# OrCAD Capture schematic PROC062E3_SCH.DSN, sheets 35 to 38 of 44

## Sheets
35 34.SERDES & DISPLAY INTERFACE: size C; title: SERDES & DISPLAY INTERFACE
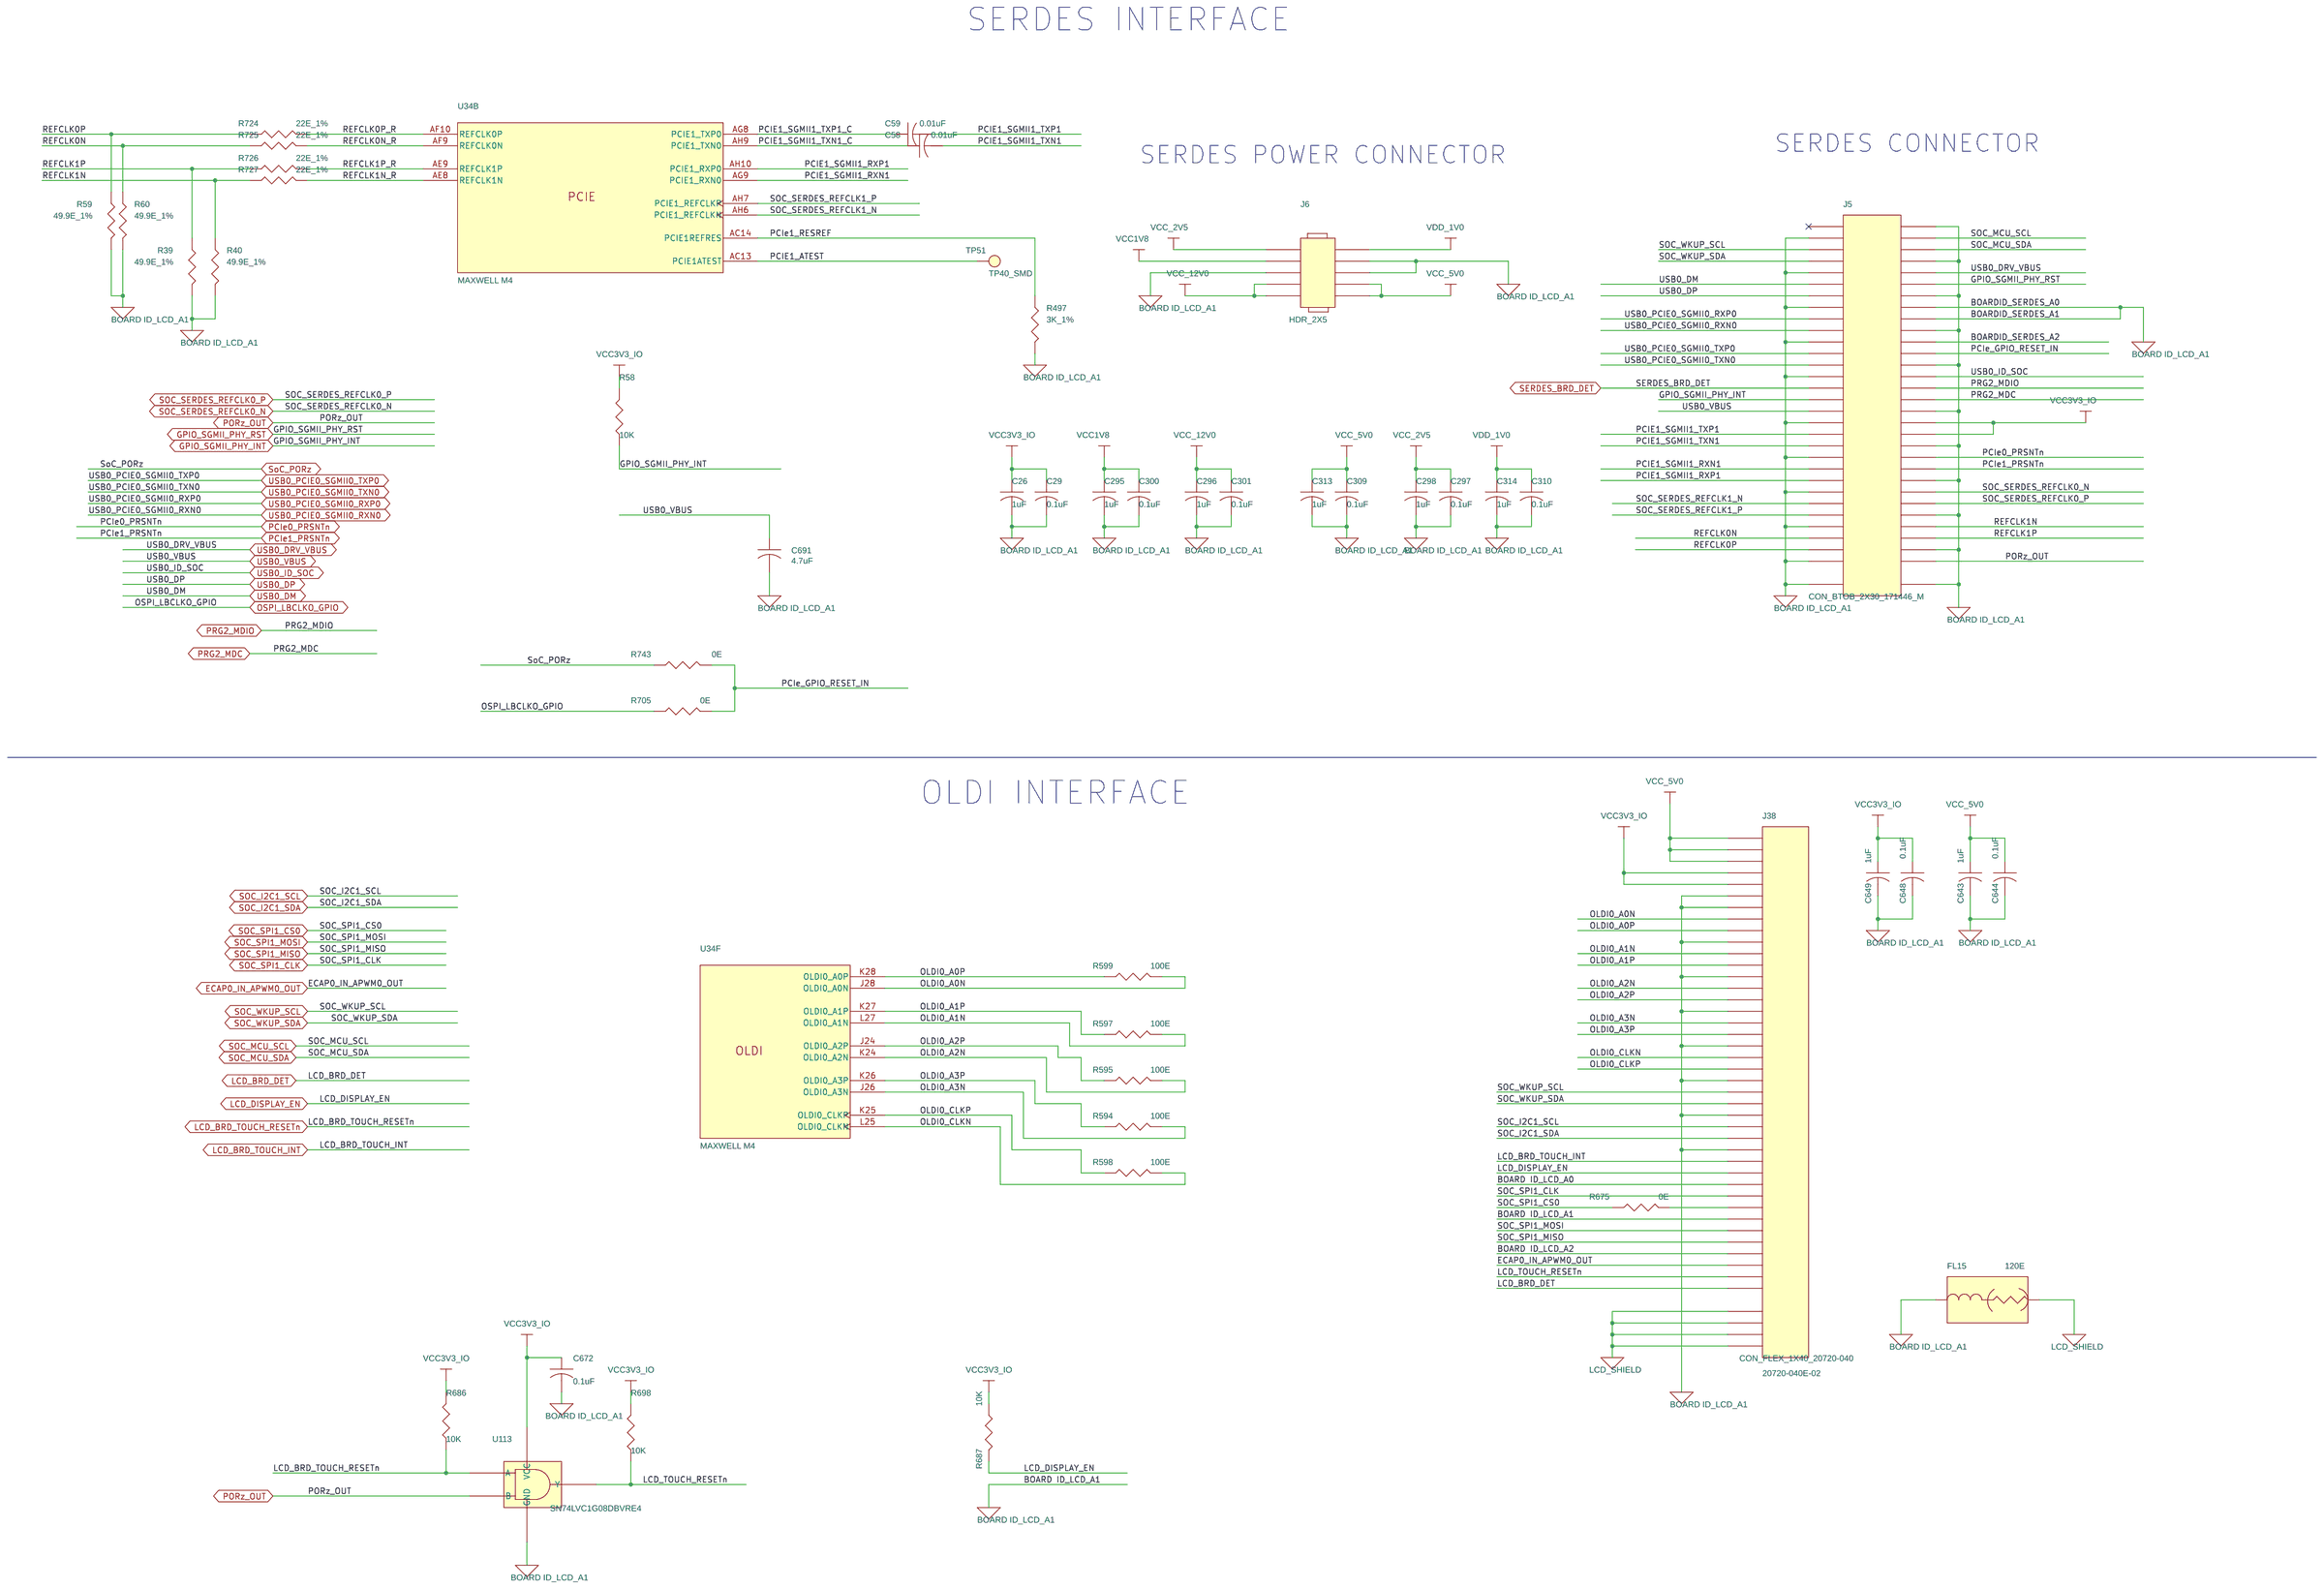
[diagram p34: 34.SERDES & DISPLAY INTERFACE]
36 36.ETHERNET PHY CLOCK BUFFER: size C; title: ETHERNET PHY CLOCK GENERATOR
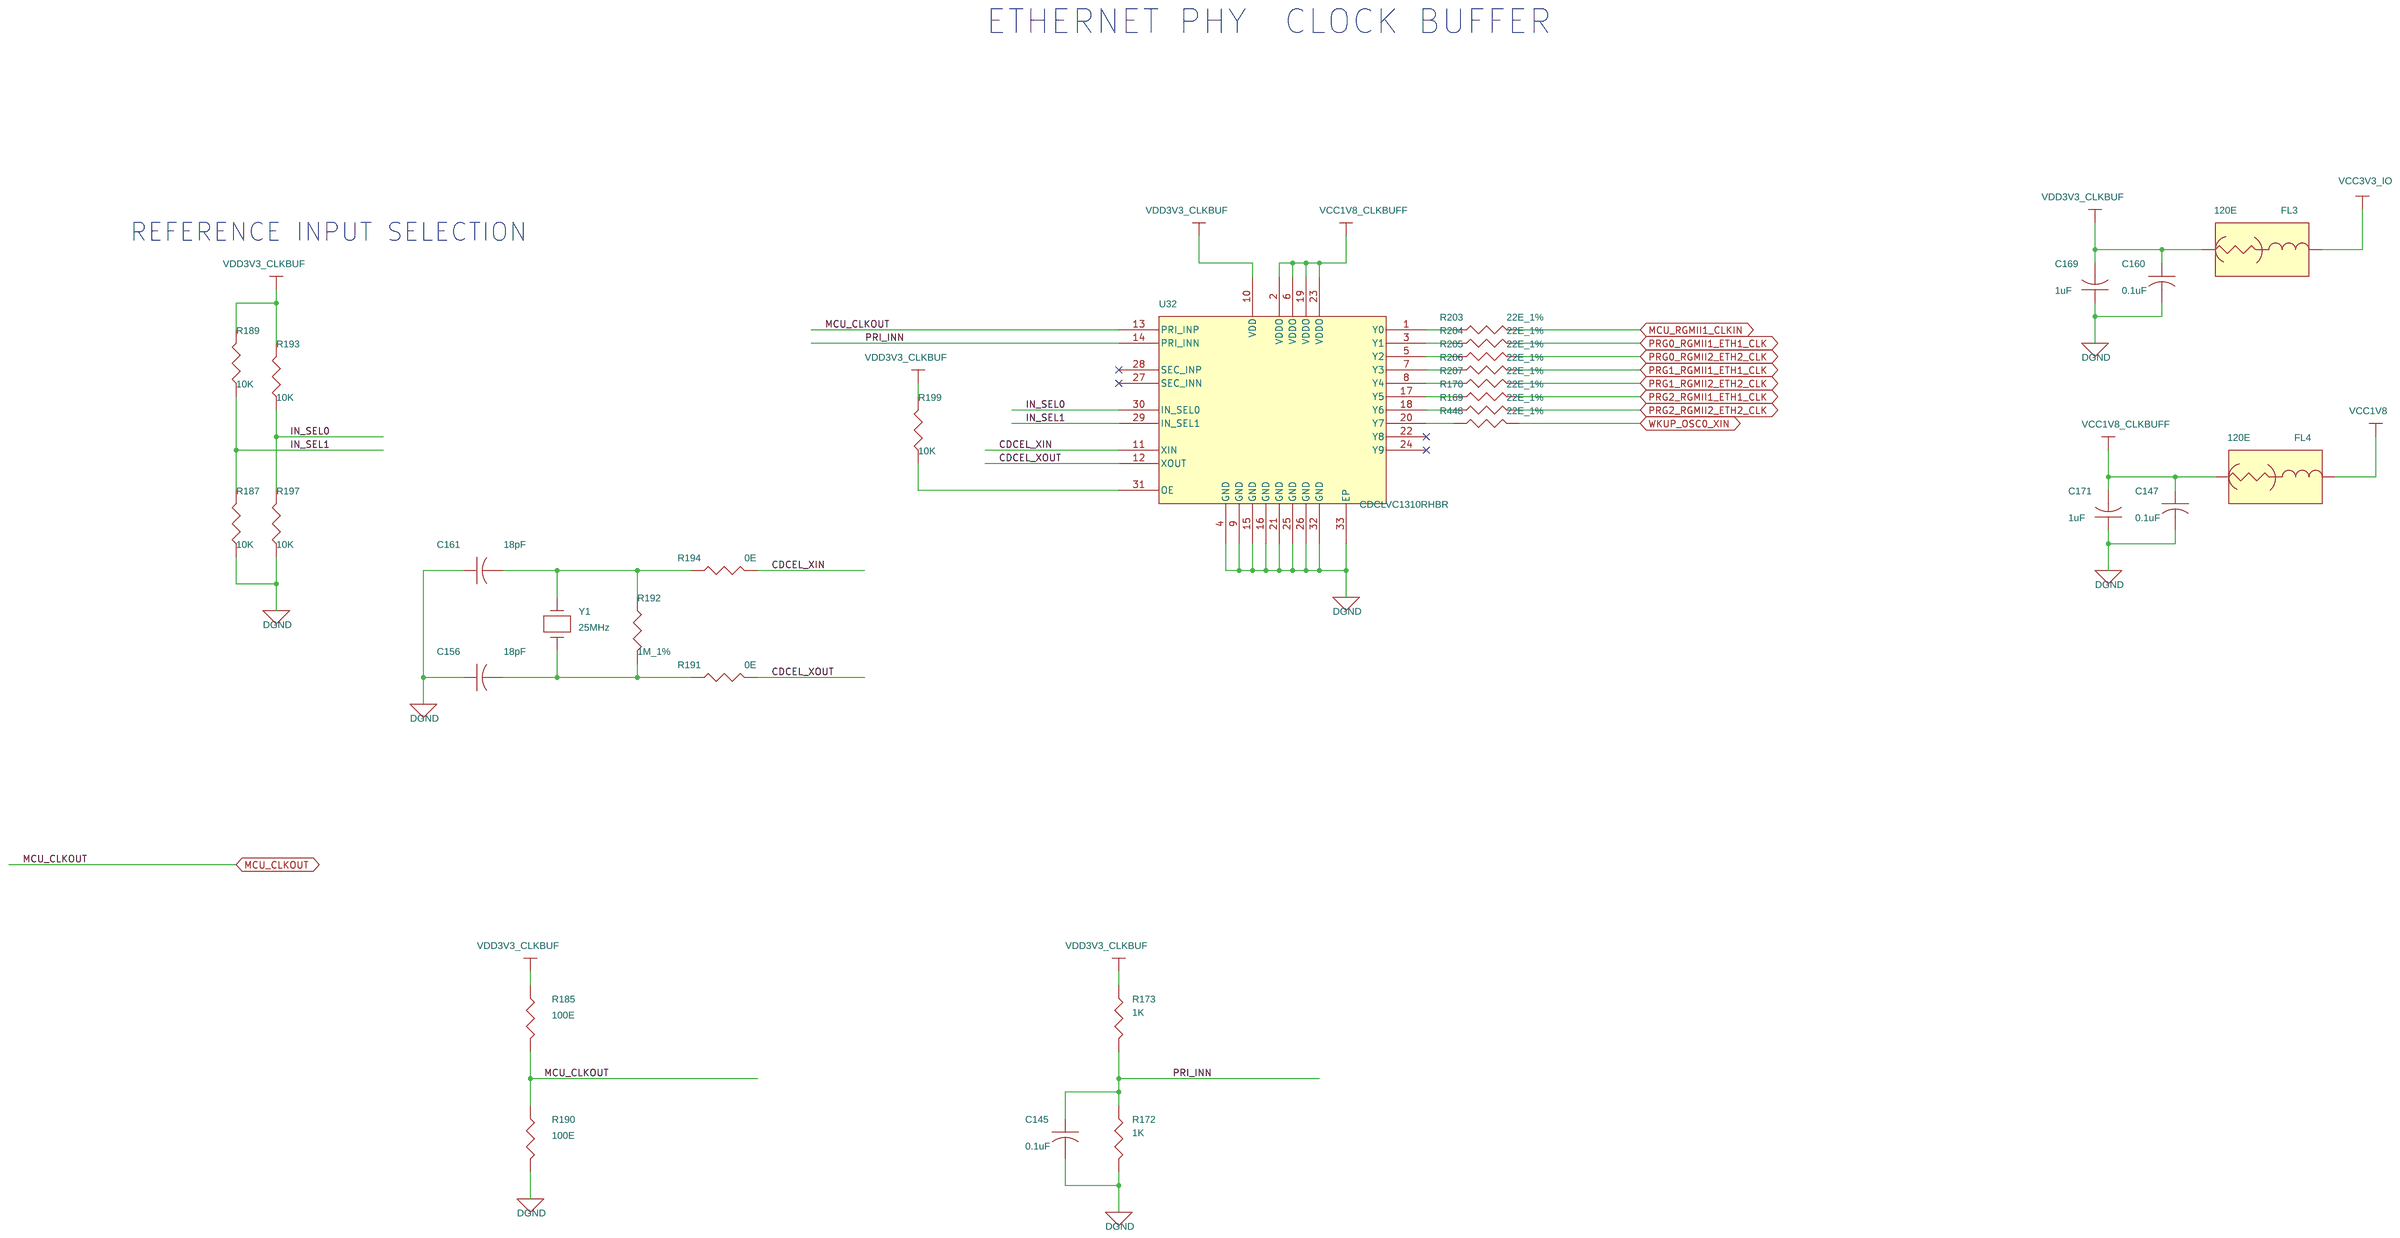
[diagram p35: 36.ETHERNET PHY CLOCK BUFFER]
37 37. ETHERNET LED's: size C; title: ETHERNET LEDs
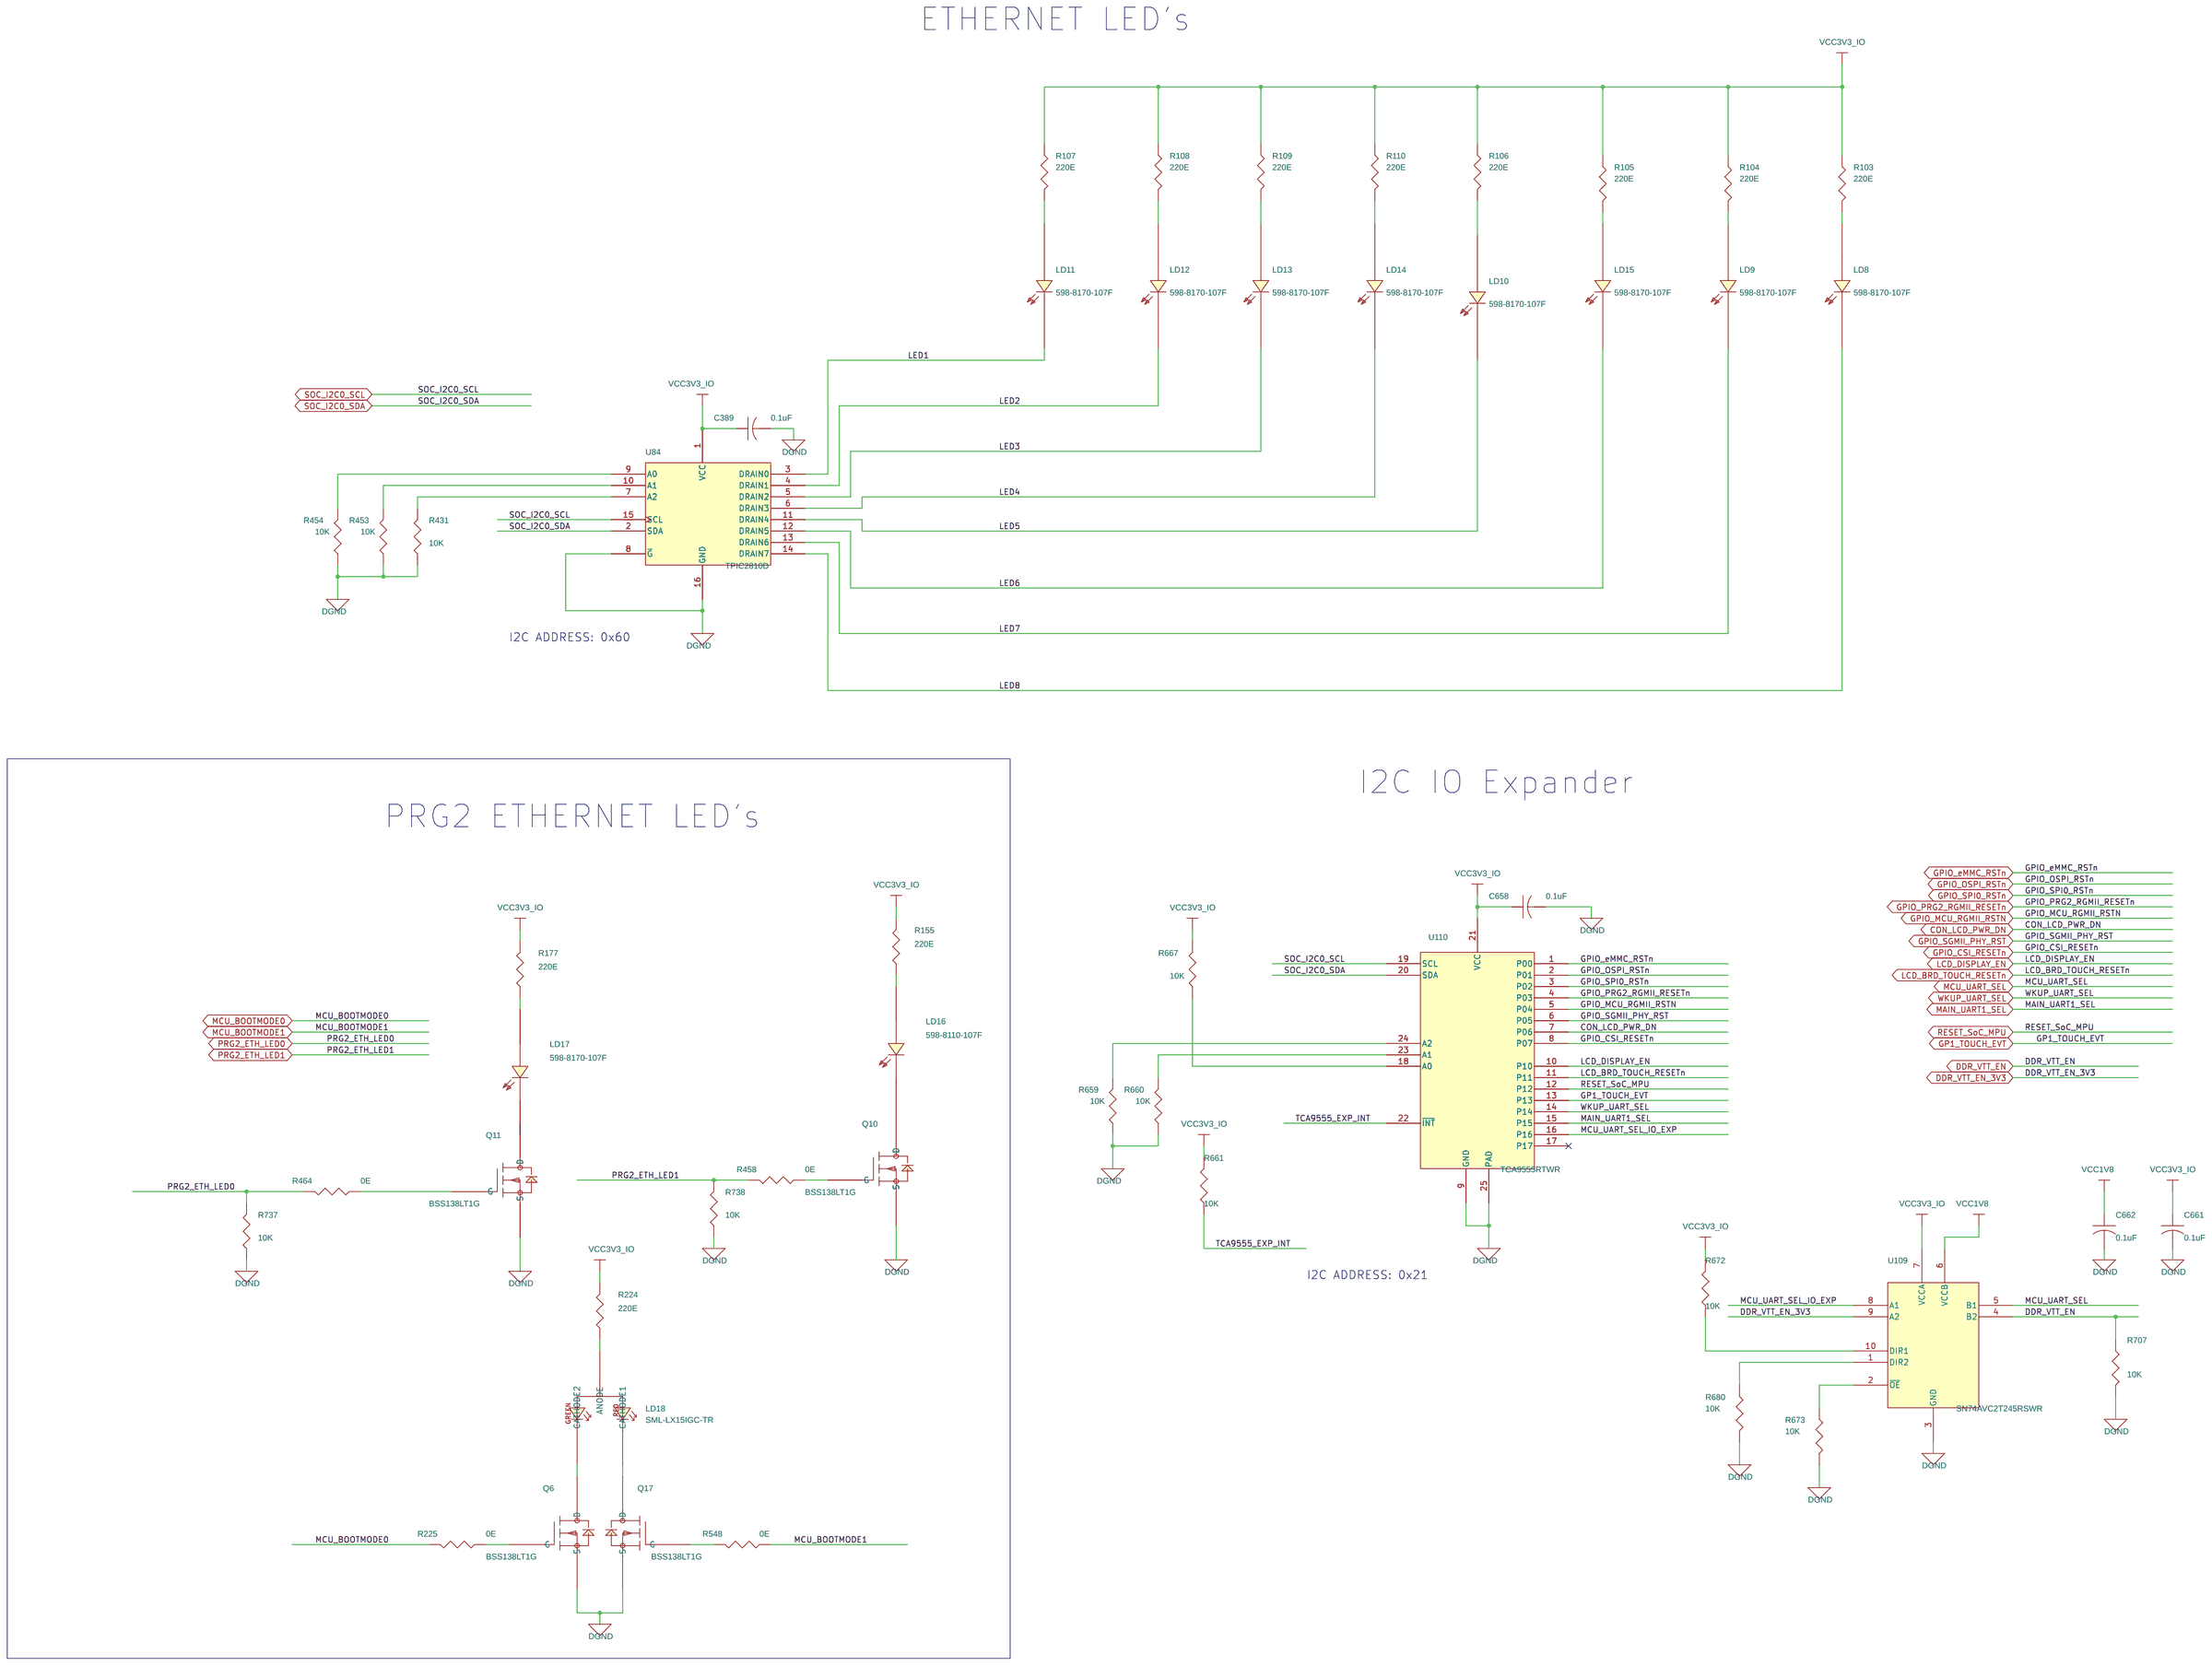
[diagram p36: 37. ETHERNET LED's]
38 38. TEST  HEADER: size C; title: TEST HEADER

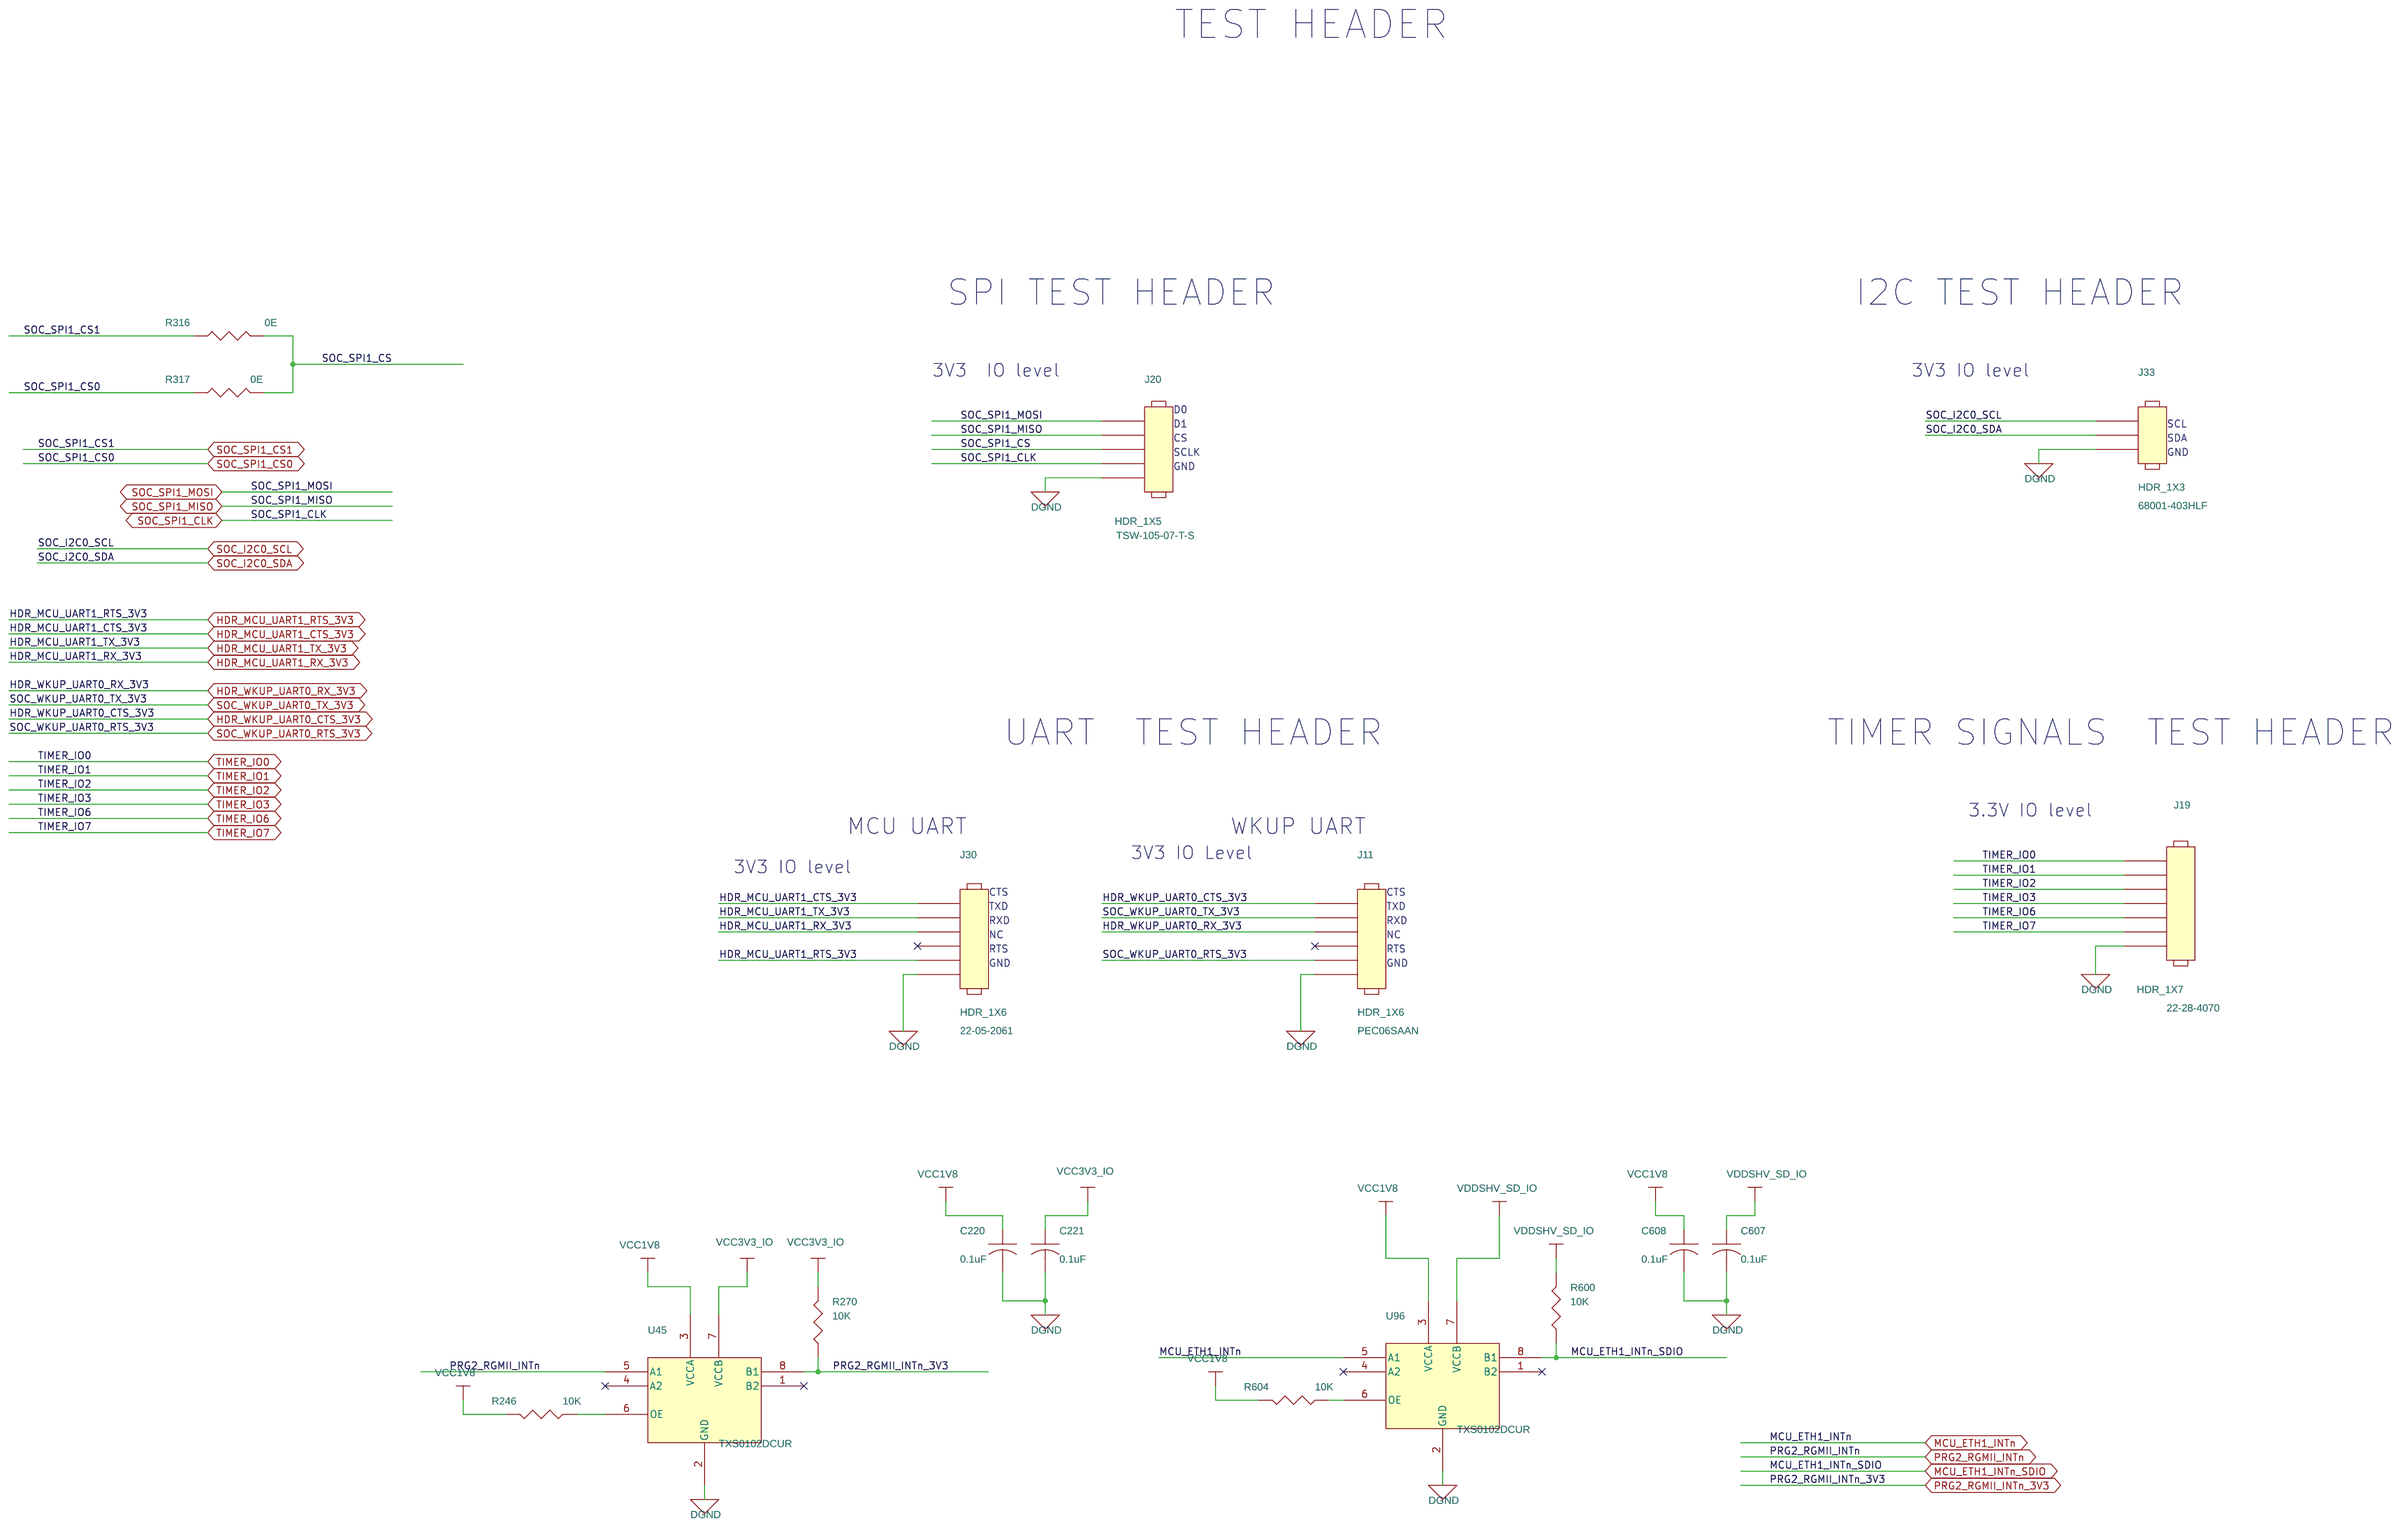
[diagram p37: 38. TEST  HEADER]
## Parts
sheet 34.SERDES & DISPLAY INTERFACE
C26  1uF  [CAP0402_0-75]
C29  0.1uF  [CAP0201_0-5]
C58  0.01uF  [CAP0402_0-75]
C59  0.01uF  [CAP0402_0-75]
C295  1uF  [CAP0402_0-75]
C296  1uF  [CAP0402_0-75]
C297  0.1uF  [CAP0201_0-5]
C298  1uF  [CAP0402_0-75]
C300  0.1uF  [CAP0201_0-5]
C301  0.1uF  [CAP0201_0-5]
C309  0.1uF  [CAP0201_0-5]
C310  0.1uF  [CAP0201_0-5]
C313  1uF  [CAP0402_0-75]
C314  1uF  [CAP0402_0-75]
C643  1uF  [CAP0402_0-75]
C644  0.1uF  [CAP0201_0-5]
C648  0.1uF  [CAP0201_0-5]
C649  1uF  [CAP0402_0-75]
C672  0.1uF  [CAP0201_0-5]
C691  4.7uF  [CAP0402_0-75]
FL15  120E  [EMIFIL_BLM15A_0402_0-6]
J5  CON_BTOB_2X30_171446_M  [CON_BTOB2X30_171446_P_S_S_5-5]
J6  HDR_2X5  [HDR_2X5_TFC-105-01-D-A_S_T_5-6]
J38  CON_FLEX_1X40_20720-040  [CON_FLEX1X40_20720-040_S_R_S_2]
R39  49.9E_1%  [RES0201]
R40  49.9E_1%  [RES0201]
R58  10K  [RES0402_0-5]
R59  49.9E_1%  [RES0201]
R60  49.9E_1%  [RES0201]
R497  3K_1%  [RES0402_0-5]
R594  100E  [RES0201]
R595  100E  [RES0201]
R597  100E  [RES0201]
R598  100E  [RES0201]
R599  100E  [RES0201]
R675  0E  [RES0402_0-5]
R686  10K  [RES0402_0-5]
R687  10K  [RES0402_0-5]
R698  10K  [RES0402_0-5]
R705  0E  [RES0402_0-5]
R724  22E_1%  [RES0402]
R725  22E_1%  [RES0402]
R726  22E_1%  [RES0402]
R727  22E_1%  [RES0402]
R743  0E  [RES0402_0-5]
TP51  TP40_SMD  [TP40_SMD]
U113  SN74LVC1G08DBVRE4  [SOT23-5]
sheet 35. CSI,GPMC/DSS INTERFACE
U34  MAXWELL M4  [BGA784_31-49_910X910_1-7]  (sections A,B,C,D,E,F,G,H,I,J,K,L,M,N,O,P,Q,R,S)
sheet 36.ETHERNET PHY CLOCK BUFFER
C145  0.1uF  [CAP0201_0-5]
C147  0.1uF  [CAP0201_0-5]
C156  18pF  [CAP0402_0-75]
C160  0.1uF  [CAP0201_0-5]
C161  18pF  [CAP0402_0-75]
C169  1uF  [CAP0402_0-75]
C171  1uF  [CAP0402_0-75]
FL3  120E  [EMIFIL_BLM15A_0402_0-6]
FL4  120E  [EMIFIL_BLM15A_0402_0-6]
R169  22E_1%  [RES0402]
R170  22E_1%  [RES0402]
R172  1K  [RES0201]
R173  1K  [RES0201]
R185  100E  [RES0402_0-5]
R187  10K  [RES0402_0-5]
R189  10K  [RES0402_0-5]
R190  100E  [RES0402_0-5]
R191  0E  [RES0402_0-5]
R192  1M_1%  [RES0402]
R193  10K  [RES0402_0-5]
R194  0E  [RES0402_0-5]
R197  10K  [RES0402_0-5]
R199  10K  [RES0402_0-5]
R203  22E_1%  [RES0402]
R204  22E_1%  [RES0402]
R205  22E_1%  [RES0402]
R206  22E_1%  [RES0402]
R207  22E_1%  [RES0402]
R448  22E_1%  [RES0402]
U32  CDCLVC1310RHBR  [QFN32_19-68_200X200_1]
Y1  25MHz  [XTAL_ABM3_210X130_SMD]
sheet 37. ETHERNET LED's
C389  0.1uF  [CAP0201_0-5]
C658  0.1uF  [CAP0201_0-5]
C661  0.1uF  [CAP0201_0-5]
C662  0.1uF  [CAP0201_0-5]
LD8  598-8170-107F  [LED_0805_0-7]
LD9  598-8170-107F  [LED_0805_0-7]
LD10  598-8170-107F  [LED_0805_0-7]
LD11  598-8170-107F  [LED_0805_0-7]
LD12  598-8170-107F  [LED_0805_0-7]
LD13  598-8170-107F  [LED_0805_0-7]
LD14  598-8170-107F  [LED_0805_0-7]
LD15  598-8170-107F  [LED_0805_0-7]
LD16  598-8110-107F  [LED_0805]
LD17  598-8170-107F  [LED_0805_0-7]
LD18  SML-LX15IGC-TR  [LED3_SML-LX15IGC_120X120_SMD_1]
Q6  BSS138LT1G  [SOT23-123]
Q10  BSS138LT1G  [SOT23-123]
Q11  BSS138LT1G  [SOT23-123]
Q17  BSS138LT1G  [SOT23-123]
R103  220E  [RES0402_0-5]
R104  220E  [RES0402_0-5]
R105  220E  [RES0402_0-5]
R106  220E  [RES0402_0-5]
R107  220E  [RES0402_0-5]
R108  220E  [RES0402_0-5]
R109  220E  [RES0402_0-5]
R110  220E  [RES0402_0-5]
R155  220E  [RES0402_0-5]
R177  220E  [RES0402_0-5]
R224  220E  [RES0402_0-5]
R225  0E  [RES0402_0-5]
R431  10K  [RES0402_0-5]
R453  10K  [RES0402_0-5]
R454  10K  [RES0402_0-5]
R458  0E  [RES0402_0-5]
R464  0E  [RES0402_0-5]
R548  0E  [RES0402_0-5]
R659  10K  [RES0402_0-5]
R660  10K  [RES0402_0-5]
R661  10K  [RES0402_0-5]
R667  10K  [RES0402_0-5]
R672  10K  [RES0402_0-5]
R673  10K  [RES0402_0-5]
R680  10K  [RES0402_0-5]
R707  10K  [RES0402_0-5]
R737  10K  [RES0402_0-5]
R738  10K  [RES0402_0-5]
U84  TPIC2810D  [SOIC16_1-8]
U109  SN74AVC2T245RSWR  [QFN10_15-74_75X60]
U110  TCA9555RTWR  [QFN24_19-68_165X165]
sheet 38. TEST  HEADER
C220  0.1uF  [CAP0201_0-5]
C221  0.1uF  [CAP0201_0-5]
C607  0.1uF  [CAP0201_0-5]
C608  0.1uF  [CAP0201_0-5]
J11  HDR_1X6  [HDR_6X1_100_S_T]
J19  HDR_1X7  [HDR_1X7_22284070_S_T_8-4]
J20  HDR_1X5  [HDR_5X1_100_S_T_8-4]
J30  HDR_1X6  [HDR_1X6_22052061_R_T_6-3]
J33  HDR_1X3  [HDR_3X1_100_S_T]
R246  10K  [RES0402_0-5]
R270  10K  [RES0402_0-5]
R316  0E  [RES0402_0-5]
R317  0E  [RES0402_0-5]
R600  10K  [RES0402_0-5]
R604  10K  [RES0402_0-5]
U45  TXS0102DCUR  [VSSOP8_19-68_85X95_0-9]
U96  TXS0102DCUR  [VSSOP8_19-68_85X95_0-9]

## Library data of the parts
C26 C169 C171 C295 C296 C298 C313 C314 C643 C649 = CAP: CAP CERAMIC 1uF 16V 20% X5R 0402; Chkd/date: MANIRAJA/150218; Crtd /date: ALVY/150218; Custom_Duty: 15%; Customs_HS_Code: 85322990; Distributor_name: DIGIKEY; Distributor_part_number: 587-5514-1-ND; Footprint Path: Y:\MIS_DATABASE\Library\ALTIUM_TOOL\PCB_FOOTPRINTS\Altium_Footprint_Lib.PcbLib; Height: 0.55MM; Library Path: Y:\MIS_DATABASE\Library\ALTIUM_TOOL\SCHEMATICS_PARTS\MS_DISCRETE_Library.schlib; Mfr_name: TAIYO YUDEN; Mfr_part_number: EMK105BJ105MV-F; Mistral Part No: 120018020006-R; Package: 0402; Part_type: CAPACITORS\CERAMIC; Project: TI_MAXIE_CPB; RoHS: RoHS; Temperature: -55°C+85°C; Tolerance: 20%; Voltage: 16V; Wattage: NA; Weight: 0.65mg; Datasheet: Y:\MIS_DATABASE\DATASHEETS\CAPACITORS\EMK105BJ105MV-F.PDF
C29 C145 C147 C160 C220 C221 C297 C300 C301 C309 C310 C389 C607 C608 C644 C648 C658 C661 C662 C672 = CAP: CAP CERAMIC 0.1uF 16V 10% X5R 0201; Chkd/date: MANIRAJA/120218; Crtd /date: MANIRAJA/120218; Custom_Duty: 15%; Customs_HS_Code: 85322990; Distributor_name: DIGIKEY; Distributor_part_number: 490-16742-1-ND; Height: 0.33MM; Mfr_name: MURATA; Mfr_part_number: GRM033R61C104KE84J; Mistral Part No: 120009030072-R; Package: 0201; Part_type: CAPACITORS\CERAMIC; Project: TI_MAXIE_CPB; RoHS: RoHS; Temperature: -55°C+85°C; Tolerance: 10%; Voltage: 16V; Wattage: NA; Weight: 0.33mg; Datasheet: Y:\MIS_DATABASE\DATASHEETS\CAPACITORS\GRM033R61C104KE84.PDF
C58 C59 = CAP: CAP CERAMIC 0.01uF 10V 10% X7R 0402; Chkd/date: VASANTHA/061216; Crtd /date: MAZHAR/201005; Custom_Duty: 15%; Customs_HS_Code: 85322990; Distributor_name: DIGIKEY; Distributor_part_number: 478-7890-1-ND; Height: 0.56MM; Mfr_name: AVX CORPORATION; Mfr_part_number: 0402ZC103KAT2A; Mistral Part No: 120009030017-R; Package: 0402; Part_type: CAPACITORS\CERAMIC; Project: ADR; RoHS: RoHS; Temperature: -55°C+125°C; Tolerance: 10%; Voltage: 10V; Wattage: NA; Weight: 0.65mg; Datasheet: Y:\MIS_DATABASE\DATASHEETS\CAPACITORS\AVX_MLC.PDF
C691 = CAP: CAP CERAMIC 4.7uF 10V 20% X5R 0402; Chkd/date: MANIRAJA/230118; Crtd /date: MANIRAJA/230118; Custom_Duty: 15%; Customs_HS_Code: 85322990; Distributor_name: DIGIKEY; Distributor_part_number: 478-10791-1-ND; Height: 0.71MM; Mfr_name: AVX CORPORATION; Mfr_part_number: 0402ZD475MAT2A; Mistral Part No: 120012060002-R; Package: 0402; Part_type: CAPACITORS\CERAMIC; Project: TI_MAXIE_CPB; RoHS: RoHS; Temperature: -55°C+85°C; Tolerance: 20%; Voltage: 10V; Wattage: NA; Weight: 0.65mg; Datasheet: Y:\MIS_DATABASE\DATASHEETS\CAPACITORS\AVX_MLC.PDF
FL3 FL4 FL15 = EMIFILTER_IND: FERRITE CHIP 120E 1.3A 0402; Chkd/date: VASANTHA/010117; Crtd /date: CHAITHANYA/150312; Custom_Duty: 24%; Customs_HS_Code: 85437099; Distributor_name: DIGIKEY; Distributor_part_number: 490-5203-1-ND; Footprint Path: Y:\MIS_DATABASE\Library\ALTIUM_TOOL\PCB_FOOTPRINTS\Altium_Footprint_Lib.PcbLib; Height: 0.55MM; Library Path: Y:\MIS_DATABASE\Library\ALTIUM_TOOL\SCHEMATICS_PARTS\MS_FILTER_Library.schlib; Mfr_name: MURATA; Mfr_part_number: BLM15PD121SN1; Mistral Part No: 130012030043-R; Package: 0402; Part_type: MISC\FILTER; Project: GEN_3-8; RoHS: RoHS; Temperature: -55°C+125°C; Tolerance: 25%; Voltage: NA; Wattage: NA; Weight: 0.65mg; Datasheet: Y:\MIS_DATABASE\DATASHEETS\DISCRETES\INDUCTORS\BLM18K-SERIES.PDF
J5 = CON_BTOB_30X2_171446: CON BTOB 2X30 0.80MM PITCH MALE ST SMD; Chkd/date: MANIRAJA/051017; Crtd /date: MANIRAJA/051017; Custom_Duty: 24%; Customs_HS_Code: 85369090; Distributor_name: DIGIKEY; Distributor_part_number: 1714461114-ND; Height: 5.50MM; Mfr_name: MOLEX; Mfr_part_number: 171446-1114; Mistral Part No: 150017100005-R; Package: SMD; Part_type: CONNECTOR\BTOB; Project: TI_MAXIE_CPB; RoHS: RoHS; Temperature: -40°C+105°C; Tolerance: NA; Voltage: NA; Wattage: NA; Weight: 526mg; Datasheet: Y:\MIS_DATABASE\DATASHEETS\CONNECTORS\171446-SER.PDF
J6 = HEADER_5X2: CON HDR 2X5 1.27MM PITCH ST TH; Chkd/date: VASANTHA/181017; Crtd /date: VASANTHA/181017; Custom_Duty: 24%; Customs_HS_Code: 85369090; Distributor_name: NA; Distributor_part_number: NA; Height: 5.59MM; Mfr_name: SAMTEC; Mfr_part_number: TFC-105-01-L-D-A; Mistral Part No: 150017100027-R; Package: THRU-HOLE; Part_type: CONNECTOR\HEADERS; Project: TI_MAXIE_CPB; RoHS: RoHS; Temperature: -55°C+125°C; Tolerance: NA; Voltage: NA; Wattage: NA; Weight: NA; Datasheet: Y:\MIS_DATABASE\DATASHEETS\CONNECTORS\TFC-TH-SERIES.PDF
J38 = CON_FLEX_40X1_SH4: CON FPC 1X40 0.50MM PITCH RT SMD; Chkd/date: MANIRAJA/121017; Crtd /date: MANIRAJA/121017; Custom_Duty: 24%; Customs_HS_Code: 85369090; Distributor_name: NA; Distributor_part_number: NA; Height: 2.00MM; Mfr_name: IPEX; Mfr_part_number: 20720-040E-02; Mistral Part No: 150017100021-R; Package: SMD; Part_type: CONNECTOR\FPC; Project: TI_MAXIE_CPB; RoHS: RoHS; Temperature: -40°C+105°C; Tolerance: NA; Voltage: NA; Wattage: NA; Weight: NA; Datasheet: Y:\MIS_DATABASE\DATASHEETS\CONNECTORS\20720-0XX.PDF
R39 R40 R59 R60 = RESISTOR: RES 49.9E 1/20W 1% 0201; Chkd/date: MAZHAR/140709; Crtd /date: MAZHAR/300807; Custom_Duty: 15%; Customs_HS_Code: 85332119; Distributor_name: DIGIKEY; Distributor_part_number: P49.9ABCT-ND; Footprint Path: Y:\MIS_DATABASE\Library\ALTIUM_TOOL\PCB_FOOTPRINTS\Altium_Footprint_Lib.PcbLib; Height: 0.26MM; Library Path: Y:\MIS_DATABASE\Library\ALTIUM_TOOL\SCHEMATICS_PARTS\MS_DISCRETE_Library.schlib; Mfr_name: PANASONIC-ECG; Mfr_part_number: ERJ-1GEF49R9C; Mistral Part No: 110009030893-R; Package: 0201; Part_type: RESISTORS\FIXED; Project: V8TS; RoHS: RoHS; Tolerance: 1%; Wattage: 1/20W; Datasheet: Y:\MIS_DATABASE\DATASHEETS\RESISTORS\ERJ-1G.PDF
R58 R187 R189 R193 R197 R199 R246 R270 R431 R453 R454 R600 R604 R659-R661 R667 R672 R673 R680 R686 R687 R698 R707 R737 R738 = RESISTOR: RES 10K 1/16W 5% 0402; Chkd/date: VASANTHA/061216; Crtd /date: MAZHAR/230805; Custom_Duty: 15%; Customs_HS_Code: 85332119; Distributor_name: DIGIKEY; Distributor_part_number: 311-10KJRCT-ND; Footprint Path: Y:\MIS_DATABASE\Library\ALTIUM_TOOL\PCB_FOOTPRINTS\Altium_Footprint_Lib.PcbLib; Height: 0.40MM; Library Path: Y:\MIS_DATABASE\Library\ALTIUM_TOOL\SCHEMATICS_PARTS\MS_DISCRETE_Library.schlib; Mfr_name: YAGEO AMERICA; Mfr_part_number: RC0402JR-0710KL; Mistral Part No: 110009030208-R; Package: 0402; Part_type: RESISTORS\FIXED; Project: HSE; RoHS: Pb-Free; Temperature: -55°C+155°C; Tolerance: 5%; Voltage: NA; Wattage: 1/16W; Weight: 0.65mg; Datasheet: Y:\MIS_DATABASE\DATASHEETS\RESISTORS\YAGEO-RC0402.PDF
R497 = RESISTOR: RES 3K 1/16W 1% 0402; Chkd/date: MANIRAJA/101117; Crtd /date: MANIRAJA/101117; Custom_Duty: 15%; Customs_HS_Code: 85332119; Distributor_name: DIGIKEY; Distributor_part_number: 311-3KLRCT-ND; Height: 0.40MM; Mfr_name: YAGEO AMERICA; Mfr_part_number: RC0402FR-073KL; Mistral Part No: 110017110004-R; Package: 0402; Part_type: RESISTORS\FIXED; Project: TI_SVB_MAXWELL_DUT; RoHS: RoHS; Temperature: -55°C+155°C; Tolerance: 1%; Voltage: NA; Wattage: 1/16W; Weight: 0.65mg; Datasheet: Y:\MIS_DATABASE\DATASHEETS\RESISTORS\YAGEO.PDF
R594 R595 R597-R599 = RESISTOR: RES 100E 1/20W 5% 0201; Chkd/date: SUHAS/280910; Crtd /date: MUDDU/100710; Custom_Duty: 15%; Customs_HS_Code: 85332119; Distributor_name: NA; Distributor_part_number: NA; Height: 0.30MM; Mfr_name: NIC COMPONENTS; Mfr_part_number: NRC02J101TRF; Mistral Part No: 110010070060-R; Package: 0201; Part_type: RESISTORS\FIXED; Project: PB_BUGBASE; RoHS: RoHS; Temperature: -55°C+125°C; Tolerance: 5%; Voltage: 50V; Wattage: 1/20W; Weight: NA; Datasheet: Y:\MIS_DATABASE\DATASHEETS\RESISTORS\NRC SERIES.PDF
R191 R194 R225 R316 R317 R458 R464 R548 R675 R705 R743 = RESISTOR: RES 0E 1/16W 0402; Chkd/date: VASANTHA/201216; Crtd /date: MUDDU/190810; Custom_Duty: 15%; Customs_HS_Code: 85332119; Distributor_name: DIGIKEY; Distributor_part_number: 541-0.0JCT-ND; Footprint Path: Y:\MIS_DATABASE\Library\ALTIUM_TOOL\PCB_FOOTPRINTS\Altium_Footprint_Lib.PcbLib; Height: 0.40MM; Library Path: Y:\MIS_DATABASE\Library\ALTIUM_TOOL\SCHEMATICS_PARTS\MS_DISCRETE_Library.schlib; Mfr_name: VISHAY; Mfr_part_number: CRCW04020000Z0ED; Mistral Part No: 110010080019-P; Package: 0402; Part_type: RESISTORS\FIXED; Project: PB_BUGBASE; RoHS: Pb-Free; Temperature: -55°C+155°C; Tolerance: NA; Voltage: NA; Wattage: 1/16W; Weight: 0.65g/1000pcs; Datasheet: Y:\MIS_DATABASE\DATASHEETS\RESISTORS\CRCW0603.PDF
R724-R727 = RESISTOR: RES 22E 1/16W 1% 0402; Alternate_mfr_name_A: VISHAY; Alternate_mfr_part_number_A: CRCW040222R0FKED; Chkd/date: SUHAS/290910; Crtd /date: MAZHAR/090909; Cust_part_number: 4700-80047E; Custom_Duty: 15%; Customs_HS_Code: 85332119; Distributor_name: DIGIKEY; Distributor_name_A: DIGIKEY; Distributor_part_number: 311-22.0LRCT-ND; Distributor_part_number_A: 541-22.0LCT-ND; Height: 0.40MM; Mfr_name: YAGEO AMERICA; Mfr_part_number: RC0402FR-0722RL; Mistral Part No: 110009090004-P; Package: 0402; Part_type: RESISTORS\FIXED; Project: VMEFMCD; Remarks: In alternate datasheet it is RoHS COMPLIANT. Y:\MIS_DATABASE\DATASHEETS\RESISTORS\CRCW0402.PDF; RoHS: Pb-Free; Temperature: -55°C+155°C; Tolerance: 1%; Voltage: 50V; Wattage: 1/16W; Weight: 0.8g/1000pcs; Datasheet: Y:\MIS_DATABASE\DATASHEETS\RESISTORS\YAGEO-RC0402.PDF
TP51 = TESTPOINT: TESTPOINT CIR 40 SMD; Chkd/date: MAZHAR/190505; Crtd /date: MAZHAR/190505; Distributor_name: NA; Distributor_part_number: NA; Footprint Path: Y:\MIS_DATABASE\Library\ALTIUM_TOOL\PCB_FOOTPRINTS\Altium_Footprint_Lib.PcbLib; Height: NA; Library Path: Y:\MIS_DATABASE\Library\ALTIUM_TOOL\SCHEMATICS_PARTS\MS_DISCRETE_Library.schlib; MECHANICAL 3D STEP FILE: NA; Mfr_name: LOCAL; Mistral Part No: 130009030933; Package: SMD; Project: RAINIER-3; RoHS: NA; Temperature: NA; Tolerance: NA; Voltage: NA; Wattage: NA; Weight: NA; Datasheet: NA
U113 = SN74LVC1G08DBVRE4_SOT23-5: IC SINGLE 2-INPUT POSITIVE AND GATE SOT23-5; Chkd/date: SUHAS/221010; Crtd /date: USMAN/151008; Custom_Duty: 15%; Customs_HS_Code: 85423100; Distributor_name: DIGIKEY; Distributor_part_number: SN74LVC1G08DBVRE4-ND; Height: 1.45MM; Mfr_name: TEXAS INSTRUMENTS; Mistral Part No: 141009060026-R; Part_type: ICS\DIGITAL\GATES; Project: KHAN_MAIN; RoHS: Sb/ Br FREE; Temperature: -40°C+85°C; Datasheet: Y:\MIS_DATABASE\DATASHEETS\ICS\DIGITAL\GATES\SN74LVC1G08.PDF
U34 = AM654X_BGA784: IC MAXWELL MICRO CONTROLLER UNIT BGA784; Chkd/date: MANIRAJA/130717; Crtd /date: MANIRAJA/130717; Custom_Duty: 15%; Customs_HS_Code: 85423100; Distributor_name: NA; Distributor_part_number: NA; Height: 1.63MM; Mfr_name: TEXAS INSTRUMENTS; Mfr_part_number: MAXWELL M4_EVM; Mistral Part No: 141217100003; Package: BGA784; Part_type: ICS\DIGITAL\MICROCONTROLLER; Project: TI_MAXIE_CPB; Temperature: NA; Tolerance: NA; Voltage: NA; Wattage: NA; Weight: NA; Datasheet: Y:\MIS_DATABASE\DATASHEETS\ICS\DIGITAL\MICROCONTROLLER\MAXWELLM4.PDF
C156 C161 = CAP: CAP CERAMIC 18pF 50V 5% C0G(NP0) 0402; Chkd/date: VASANTHA/150514; Crtd /date: BALACHANDAR/150514; Custom_Duty: 15%; Customs_HS_Code: 85322990; Distributor_name: DIGIKEY; Distributor_part_number: 490-5858-1-ND; Footprint Path: Y:\MIS_DATABASE\Library\ALTIUM_TOOL\PCB_FOOTPRINTS\Altium_Footprint_Lib.PcbLib; Height: 0.55MM; Library Path: Y:\MIS_DATABASE\Library\ALTIUM_TOOL\SCHEMATICS_PARTS\MS_DISCRETE_Library.schlib; Mfr_name: MURATA; Mfr_part_number: GRM1555C1H180JA01D; Mistral Part No: 120014050002-R; Package: 0402; Part_type: CAPACITORS\CERAMIC; Project: HUMANWARE_PHOENIX; RoHS: RoHS; Temperature: -55°C+125°C; Tolerance: 5%; Voltage: 50V; Wattage: NA; Weight: 6mg; Datasheet: Y:\MIS_DATABASE\DATASHEETS\CAPACITORS\GRM188SERIES.PDF
R169 R170 R203-R207 R448 = RESISTOR: RES 22E 1/16W 1% 0402; Alternate_mfr_name_A: VISHAY; Alternate_mfr_part_number_A: CRCW040222R0FKED; Chkd/date: SUHAS/290910; Crtd /date: MAZHAR/090909; Cust_part_number: 4700-80047E; Custom_Duty: 15%; Customs_HS_Code: 85332119; Distributor_name: DIGIKEY; Distributor_name_A: DIGIKEY; Distributor_part_number: 311-22.0LRCT-ND; Distributor_part_number_A: 541-22.0LCT-ND; Height: 0.40MM; Mfr_name: YAGEO AMERICA; Mfr_part_number: RC0402FR-0722RL; Mistral Part No: 110009090004-P; Package: 0402; Part_type: RESISTORS\FIXED; Project: VMEFMCD; Remarks: In alternate datasheet it is RoHS COMPLIANT. Y:\MIS_DATABASE\DATASHEETS\RESISTORS\CRCW0402.PDF; RoHS: Pb-Free; SIGNAL_MODEL: RESISTOR_RES0402_22E_22E; Temperature: -55°C+155°C; Tolerance: 1%; Voltage: 50V; Wattage: 1/16W; Weight: 0.8g/1000pcs; Datasheet: Y:\MIS_DATABASE\DATASHEETS\RESISTORS\YAGEO-RC0402.PDF
R172 R173 = RESISTOR: RES 1K 1/20W 5% 0201; Chkd/date: JEBRAN/110815; Crtd /date: JEBRAN/110815; Custom_Duty: 15%; Customs_HS_Code: 85332119; Distributor_name: DIGIKEY; Distributor_part_number: 541-1.00KAABCT-ND; Height: 0.28MM; Mfr_name: VISHAY; Mfr_part_number: CRCW02011K00FKED; Mistral Part No: 110015080014-R; Package: 0201; Part_type: RESISTORS\FIXED; Project: OCTASIC_3000; RoHS: RoHS; Temperature: -55°C+155°C; Tolerance: 5%; Voltage: NA; Wattage: 1/20W; Weight: NA; Datasheet: Y:\MIS_DATABASE\DATASHEETS\RESISTORS\CRCW0201.PDF
R185 R190 = RESISTOR: RES 100E 1/16W 5% 0402; Chkd/date: MANIRAJA/230817; Crtd /date: MANIRAJA/230817; Custom_Duty: 15%; Customs_HS_Code: 85332119; Distributor_name: DIGIKEY; Distributor_part_number: 541-100JCT-ND; Height: 0.40MM; Mfr_name: VISHAY; Mfr_part_number: CRCW0402100RJNED; Mistral Part No: 110009030164-R; Package: 0402; Part_type: RESISTORS\FIXED; Project: TI_MAXIE_CPB; RoHS: RoHS; Temperature: -55°C+155°C; Tolerance: 5%; Voltage: NA; Wattage: 1/16W; Weight: 0.65mg; Datasheet: Y:\MIS_DATABASE\DATASHEETS\RESISTORS\CRCW0603.PDF
R192 = RESISTOR: RES 1M 1/16W 1% 0402; Chkd/date: VASANTHA/200614; Crtd /date: NAVEED/170614; Custom_Duty: 15%; Customs_HS_Code: 85332119; Distributor_name: DIGIKEY; Distributor_part_number: RMCF0402FT1M00CT-ND; Footprint Path: Y:\MIS_DATABASE\Library\ALTIUM_TOOL\PCB_FOOTPRINTS\Altium_Footprint_Lib.PcbLib; Height: 0.40MM; Library Path: Y:\MIS_DATABASE\Library\ALTIUM_TOOL\SCHEMATICS_PARTS\MS_DISCRETE_Library.schlib; Mfr_name: STACKPOLE ELECTRONICS; Mfr_part_number: RMCF0402FT1M00; Mistral Part No: 110014060045-R; Package: 0402; Part_type: RESISTORS\FIXED; Project: AEGIS_POM; RoHS: RoHS; Temperature: -55°C+155°C; Tolerance: 1%; Voltage: NA; Wattage: 1/16W; Weight: 0.57mg; Datasheet: Y:\MIS_DATABASE\DATASHEETS\RESISTORS\RMCF-SERIES1.PDF
U32 = CDCLVC1310RHBR_VQFN32: IC LOW JITTER,LOW POWER CLK BUFFER LEVEL TRANSLATOR VQFN32; Chkd/date: MANIRAJA/061017; Crtd /date: MANIRAJA/061017; Custom_Duty: 15%; Customs_HS_Code: 85423100; Distributor_name: DIGIKEY; Distributor_part_number: 296-30105-1-ND; Height: 1.00MM; Mfr_name: TEXAS INSTRUMENTS; Mistral Part No: 141017100003-R; Package: VQFN32; Part_type: ICS\INTERFACE\LEVEL TRANSLATOR; Project: TI_MAXIE_CPB; RoHS: RoHS; Temperature: -40°C+85°C; Tolerance: NA; Voltage: NA; Wattage: NA; Weight: 72.2mg; Datasheet: Y:\MIS_DATABASE\DATASHEETS\ICS\INTERFACE\CDCLVC1310RHBR.PDF
Y1 = CRY: CRY 25MHz SMD; Chkd/date: BAVISH/041011; Crtd /date: CHAITHANYA/041011; Custom_Duty: 24%; Customs_HS_Code: 85439000; Distributor_name: DIGIKEY; Distributor_part_number: 535-10645-1-ND; Height: 1.50MM; Mfr_name: ABRACON; Mfr_part_number: ABM3-25.000MHZ-D2Y-T; Mistral Part No: 130011100003-R; Package: SMD; Part_type: CRYSTAL; Project: VP-4000-PROCESSOR; RoHS: RoHS; Temperature: -40°C+85°C; Tolerance: NA; Voltage: NA; Wattage: NA; Weight: NA; Datasheet: Y:\MIS_DATABASE\DATASHEETS\MISC\CRY_OSC\ABM3.PDF
LD8-LD15 LD17 = LED_598-8170-107F: LED ALINGAP GREEN CLEAR 0805; Chkd/date: MANIRAJA/230817; Crtd /date: SARANYA/070514; Custom_Duty: 24%; Customs_HS_Code: 85437099; Distributor_name: DIGIKEY; Distributor_part_number: 350-2044-1-ND; Height: 0.70MM; Mfr_name: DIALIGHT; Mistral Part No: 130014050065-R; Package: 0805; Part_type: OPTO\LED; Project: AEGIS GP BETA2; RoHS: RoHS; Temperature: -30°C+85°C; Tolerance: NA; Voltage: NA; Wattage: NA; Weight: NA; Datasheet: Y:\MIS_DATABASE\DATASHEETS\DISCRETES\LEDS\598-SER.PDF
LD16 = LED_598-8170-107F: LED ALINGAP RED CLEAR 0805 SMD; Chkd/date: BALACHANDAR/160514; Crtd /date: SARANYA/070514; Custom_Duty: 24%; Customs_HS_Code: 85437099; Distributor_name: DIGIKEY; Distributor_part_number: 350-2038-1-ND; Height: 0.70MM; Mfr_name: DIALIGHT; Mistral Part No: 130014050069-R; Package: 0805; Part_type: OPTO\LED; Project: AEGIS GP BETA2; RoHS: RoHS; Temperature: NA; Tolerance: NA; Voltage: NA; Wattage: NA; Weight: NA; Datasheet: Y:\MIS_DATABASE\DATASHEETS\DISCRETES\LEDS\598-SER.PDF
LD18 = LED3_SML-LX15IGC: DIODE LED GREEN/RED SMD; Chkd/date: MANIRAJA/180917; Crtd /date: MANIRAJA/180917; Custom_Duty: 24%; Customs_HS_Code: 85439000; Distributor_name: DIGIKEY; Distributor_part_number: 67-2193-1-ND; Height: 1.00MM; Mfr_name: LUMEX; Mistral Part No: 130017090021-R; Package: SMD; Part_type: OPTO\LED; Project: TI_MAXIE_CPB; RoHS: RoHS; Temperature: -40°C+85°C; Tolerance: NA; Voltage: NA; Wattage: NA; Weight: NA; Datasheet: Y:\MIS_DATABASE\DATASHEETS\DISCRETES\LEDS\SML-LX15IGC.PDF
Q6 Q10 Q11 Q17 = MOSFET_BSS138LT1G: IC MOSFET N-CHANNEL 50V, SOT23-3; Chkd/date: VASANTHA/150416; Crtd /date: JEBRAN/060416; Custom_Duty: 15%; Customs_HS_Code: 85423100; Distributor_name: MOUSER; Distributor_part_number: 863-BSS138LT1G; Height: 1.11MM; Mfr_name: ON SEMICONDUCTOR; Mistral Part No: 142016040001-R; Package: SOT23-3; Part_type: ICS\POWER\MOSFET; Project: LRDE_ABCM; RoHS: RoHS; Temperature: -55°C+150°C; Tolerance: NA; Voltage: 50V; Wattage: NA; Weight: NA; Datasheet: Y:\MIS_DATABASE\DATASHEETS\DISCRETES\TRANSISTORS_FETS\BSS138LT1G.PDF
R103-R110 R155 R177 R224 = RESISTOR: RES 220E 1/16W 5% 0402; Chkd/date: VASANTHA/291216; Crtd /date: GEETHA/260406; Custom_Duty: 15%; Customs_HS_Code: 85332119; Distributor_name: DIGIKEY; Distributor_part_number: P220JCT-ND; Footprint Path: Y:\MIS_DATABASE\Library\ALTIUM_TOOL\PCB_FOOTPRINTS\Altium_Footprint_Lib.PcbLib; Height: 0.40MM; Library Path: Y:\MIS_DATABASE\Library\ALTIUM_TOOL\SCHEMATICS_PARTS\MS_DISCRETE_Library.schlib; Mfr_name: PANASONIC-ECG; Mfr_part_number: ERJ-2GEJ221X; Mistral Part No: 110009030506-R; Package: 0402; Part_type: RESISTORS\FIXED; Project: RED EYE; RoHS: RoHS; Temperature: -55°C+155°C; Tolerance: 5%; Voltage: NA; Wattage: 1/16W; Weight: 0.8g/1000pcs; Datasheet: Y:\MIS_DATABASE\DATASHEETS\RESISTORS\ERJ12.PDF
U84 = TPIC2810D_SOIC16: IC 8-BIT LED DRIVER WITH I2C INTERFACE SOIC16; Chkd/date: MANIRAJA/230817; Crtd /date: MANIRAJA/220817; Custom_Duty: 15%; Customs_HS_Code: 85423100; Distributor_name: DIGIKEY; Distributor_part_number: 296-13746-5-ND; Height: 1.75MM; Mfr_name: TEXAS INSTRUMENTS; Mistral Part No: 141017080026-R; Package: SOIC16; Part_type: ICS\INTERFACE; Project: TI_MAXIE_CPB; RoHS: RoHS; Temperature: -40°C+125°C; Tolerance: NA; Voltage: NA; Wattage: NA; Weight: NA; Datasheet: Y:\MIS_DATABASE\DATASHEETS\ICS\INTERFACE\TPIC2810D.PDF
U109 = SN74AVC2T245RSWR_QFN10: IC DUAL-BIT DUAL SUPPLY BUS TRANSCEIVER QFN10; Chkd/date: SUHAS/031110; Crtd /date: USMAN/130309; Custom_Duty: 15%; Customs_HS_Code: 85423100; Distributor_name: DIGIKEY; Distributor_part_number: 296-23684-1-ND; Height: 0.55MM; Mfr_name: TEXAS INSTRUMENTS; Mistral Part No: 143009030061-R; Package: QFN10; Part_type: ICS\TELECOM\TRANSCEIVER; Project: AXON; RoHS: Sb/ Br FREE; Temperature: -40°C+85°C; Datasheet: Y:\MIS_DATABASE\DATASHEETS\ICS\DIGITAL\BUSTRANSCEIVER\SN74AVC2T245RSWR.PDF
U110 = TCA9555RTWR_WQFN24: IC I/O EXPANDER I2C BUS 16-BIT WQFN24; Chkd/date: USMAN/120913; Crtd /date: VIJAYALAKSHMI/200813; Distributor_name: DIGIKEY; Distributor_part_number: 296-24857-1-ND; Height: 0.80MM; Mfr_name: TEXAS INSTRUMENTS; Mistral Part No: 141013080010-R; Package: WQFN24; Part_type: ICS\DIGITAL\BUSTRANSCEIVER; Project: RTM; RoHS: RoHS; Temperature: -40°C+85°C; Tolerance: NA; Voltage: NA; Wattage: NA; Weight: NA; Datasheet: Y:\MIS_DATABASE\DATASHEETS\ICS\DIGITAL\BUSTRANSCEIVER\TCA9555X.PDF
J11 = HEADER_6X1: HDR 1X6 2.54 PITCH ST TH; Chkd/date: VASANTHA/220616; Crtd /date: VASANTHA/220616; Custom_Duty: 24%; Customs_HS_Code: 85369090; Distributor_name: DIGIKEY; Distributor_part_number: S1012E-06-ND; Height: 8.38MM; Mfr_name: SULLINS; Mfr_part_number: PEC06SAAN; Mistral Part No: 150016060022-R; Package: THRU HOLE; Part_type: CONNECTOR\HEADERS; Project: NTR_GPSDO BOX CARD; RoHS: RoHS; Temperature: -65°C+125°C; Tolerance: NA; Voltage: NA; Wattage: NA; Weight: NA; Datasheet: Y:\MIS_DATABASE\DATASHEETS\CONNECTORS\PECXXX_SERIES.PDF
J19 = HEADER_7X1: CON HDR 1X7 2.54MM PITCH ST TH; Chkd/date: MANIRAJA/230118; Crtd /date: ALVY/230118; Custom_Duty: 24%; Customs_HS_Code: 85369090; Distributor_name: DIGIKEY; Distributor_part_number: WM50014-07-ND; Height: 8.38MM; Mfr_name: MOLEX; Mfr_part_number: 22-28-4070; Mistral Part No: 150018010021-R; Package: THRU-HOLE; Part_type: CONNECTOR\HEADERS; Project: TI_MAXIE_CPB; RoHS: RoHS; Temperature: NA; Tolerance: NA; Voltage: NA; Wattage: NA; Weight: 431mg; Datasheet: Y:\MIS_DATABASE\DATASHEETS\CONNECTORS\22-28-SER.PDF
J20 = HEADER_5X1: CON HDR 1X5 2.54MM PITCH ST TH; Chkd/date: MANIRAJA/010917; Crtd /date: MANIRAJA/010917; Custom_Duty: 24%; Customs_HS_Code: 85369090; Distributor_name: DIGIKEY; Distributor_part_number: SAM1035-05-ND; Height: 8.38MM; Mfr_name: SAMTEC; Mfr_part_number: TSW-105-07-T-S; Mistral Part No: 150017090001-R; Package: THRU-HOLE; Part_type: CONNECTOR\HEADERS; Project: TI_MAXIE_CPB; RoHS: RoHS; Temperature: -55°C+105°C; Tolerance: NA; Voltage: NA; Wattage: NA; Weight: NA; Datasheet: Y:\MIS_DATABASE\DATASHEETS\CONNECTORS\TSW-MK.PDF
J30 = HEADER_6X1: CON HDR 1X6 2.54MM PITCH RT TH; Chkd/date: MANIRAJA/240118; Crtd /date: MANIRAJA/240118; Custom_Duty: 24%; Customs_HS_Code: 85369090; Distributor_name: DIGIKEY; Distributor_part_number: WM4104-ND; Height: 6.30MM; Mfr_name: MOLEX; Mfr_part_number: 22-05-2061; Mistral Part No: 150018010023-R; Package: THRU-HOLE; Part_type: CONNECTOR\HEADERS; Project: TI_MAXIE_CPB; RoHS: RoHS; Temperature: NA; Tolerance: NA; Voltage: NA; Wattage: NA; Weight: 484mg; Datasheet: Y:\MIS_DATABASE\DATASHEETS\CONNECTORS\A-4094-SER.PDF
J33 = HEADER_3X1: HDR 1X3 2.54MM PITCH ST TH; Chkd/date: VASANTHA/290616; Crtd /date: VASANTHA/290616; Custom_Duty: 15%; Customs_HS_Code: 85322990; Distributor_name: DIGIKEY; Distributor_part_number: 609-3471-ND; Height: 8.58MM; Mfr_name: FCI; Mfr_part_number: 68001-403HLF; Mistral Part No: 150016060025-R; Package: THRU-HOLE; Part_type: CONNECTOR\HEADERS; Project: IKEYP; RoHS: RoHS; Temperature: -40°C+105°C; Tolerance: NA; Voltage: NA; Wattage: NA; Weight: NA; Datasheet: Y:\MIS_DATABASE\DATASHEETS\CONNECTORS\68000.PDF
U45 U96 = TXS0102DCUR_VSSOP8: IC 2BIT BI-DIR VOLTAGE-LEVEL TRANSLATOR US8(VSSOP8); Chkd/date: MANIRAJA/130617; Crtd /date: SHREESHAIL/190108; Custom_Duty: 15%; Customs_HS_Code: 85423100; Distributor_name: DIGIKEY; Distributor_part_number: 296-21931-1-ND; Footprint Path: Y:\MIS_DATABASE\Library\ALTIUM_TOOL\PCB_FOOTPRINTS\Altium_Footprint_Lib.PcbLib; Height: 0.90MM; Library Path: Y:\MIS_DATABASE\Library\ALTIUM_TOOL\SCHEMATICS_PARTS\MS_MISCINTERFACE_Library.schlib; Mfr_name: TEXAS INSTRUMENTS; Mistral Part No: 141009030376-R; Package: US8; Part_type: ICS\INTERFACE\LEVEL TRANSLATOR; Project: SD_WATERLOO; RoHS: RoHS; Temperature: -40°C+85°C; Tolerance: NA; Voltage: NA; Wattage: NA; Weight: 9.6mg; Datasheet: Y:\MIS_DATABASE\DATASHEETS\ICS\INTERFACE\TXS0102.PDF

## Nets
DGND: C26.2 C29.2 C145.2 C147.2 C156.1 C160.2 C161.1 C169.1 C171.1 C220.2 C221.2 C295.2 C296.2 C297.2 C298.2 C300.2 C301.2 C309.2 C310.2 C313.2 C314.2 C389.2 C607.2 C608.2 C643.2 C644.2 C648.2 C649.2 C658.2 C661.2 C662.2 C672.2 C691.2 FL15.1 J5.1 J5.4 J5.7 J5.8 J5.9 J5.10 J5.13 J5.17 J5.20 J5.23 J5.26 J5.29 J5.32 J5.35 J5.38 J5.41 J5.44 J5.48 J5.51 J5.54 J5.57 J5.60 J5.SH1 J5.SH2 J6.4 J6.5 J6.6 J11.1 J19.7 J20.5 J30.1 J33.1 J38.6 J38.7 J38.10 J38.13 J38.16 J38.19 J38.22 J38.25 J38.28 J38.34 Q6.2(S) Q10.2(S) Q11.2(S) Q17.2(S) R39.2 R40.2 R59.2 R60.2 R172.2 R187.1 R190.2 R197.1 R431.1 R453.1 R454.1 R497.2 R659.1 R660.1 R673.2 R680.2 R707.2 R737.1 R738.1 U32.4(GND) U32.9(GND) U32.15(GND) U32.16(GND) U32.21(GND) U32.25(GND) U32.26(GND) U32.32(GND) U32.33(EP) U45.2(GND) U84.8(~{G}) U84.16(GND) U96.2(GND) U109.3(GND) U110.9(GND) U110.25(PAD) U113.3(GND) ; also on sheet 11 12 13 14 15 16 17 18 19 20 21 22 23 24 25 26 27 28 29 30 31 32 33 34 39 40 41 42 43 44
VCC1V8: C220.1 C295.1 C300.1 C608.1 C662.1 FL4.1 J6.3 R246.2 R604.2 U45.3(VCCA) U96.3(VCCA) U109.6(VCCB) ; also on sheet 11 18 19 20 21 22 23 26 29 31 33 41 44
VCC1V8_CLKBUFF: C147.1 C171.2 FL4.2 U32.2(VDDO) U32.6(VDDO) U32.19(VDDO) U32.23(VDDO)
VCC3V3_IO: C26.1 C29.1 C221.1 C389.1 C648.1 C649.1 C658.1 C661.1 C672.1 FL3.1 J5.18 J5.19 J38.4 J38.5 R58.2 R103.1 R104.1 R105.1 R106.1 R107.1 R108.1 R109.1 R110.1 R155.2 R177.2 R224.2 R270.2 R661.2 R667.2 R672.2 R686.2 R687.1 R698.2 U45.7(VCCB) U84.1(VCC) U109.7(VCCA) U110.21(VCC) U113.5(VCC) ; also on sheet 11 18 19 20 21 22 23 24 25 26 28 29 30 31 33 34 39 41 42 44
VCC_2V5: C297.1 C298.1 J6.1 ; also on sheet 17 42
VCC_5V0: C309.1 C313.1 C643.1 C644.1 J6.8 J6.10 J38.1 J38.2 J38.3 ; also on sheet 30 33 40 44
VCC_12V0: C296.1 C301.1 J6.7 J6.9 ; also on sheet 40 43
VDD3V3_CLKBUF: C160.1 C169.2 FL3.2 R173.1 R185.1 R189.2 R193.2 R199.2 U32.10(VDD)
VDD_1V0: C310.1 C314.1 J6.2 ; also on sheet 21 22 23 33 42
VDDSHV_SD_IO: C607.1 R600.2 U96.7(VCCB) ; also on sheet 13 18
BOARD ID_LCD_A0: J38.31
BOARD ID_LCD_A2: J38.37
BOARDID_SERDES_A2: J5.11
CDCEL_XIN: R194.2 U32.11(XIN)
CDCEL_XOUT: R191.2 U32.12(XOUT)
CON_LCD_PWR_DN: U110.7(P06) ; also on sheet 44
DDR_VTT_EN: R707.1 U109.4(B2) ; also on sheet 19
DDR_VTT_EN_3V3: U109.9(A2) ; also on sheet 42
ECAP0_IN_APWM0_OUT: J38.38 ; also on sheet 34
GP1_TOUCH_EVT: U110.13(P13) ; also on sheet 44
GPIO_CSI_RESETn: U110.8(P07) ; also on sheet 44
GPIO_eMMC_RSTn: U110.1(P00) ; also on sheet 18
GPIO_MCU_RGMII_RSTN: U110.5(P04) ; also on sheet 23
GPIO_OSPI_RSTn: U110.2(P01) ; also on sheet 19
GPIO_PRG2_RGMII_RESETn: U110.4(P03) ; also on sheet 21
GPIO_SGMII_PHY_INT: J5.46 R58.1 ; also on sheet 34
GPIO_SGMII_PHY_RST: J5.6 U110.6(P05)
GPIO_SPI0_RSTn: U110.3(P02) ; also on sheet 19
HDR_MCU_UART1_CTS_3V3: J30.6 ; also on sheet 31
HDR_MCU_UART1_RTS_3V3: J30.2 ; also on sheet 31
HDR_MCU_UART1_RX_3V3: J30.4 ; also on sheet 31
HDR_MCU_UART1_TX_3V3: J30.5 ; also on sheet 31
HDR_WKUP_UART0_CTS_3V3: J11.6 ; also on sheet 31
HDR_WKUP_UART0_RX_3V3: J11.4 ; also on sheet 31
IN_SEL0: R193.1 R197.2 U32.30(IN_SEL0)
IN_SEL1: R187.2 R189.1 U32.29(IN_SEL1)
LCD_BRD_DET: J38.40 ; also on sheet 20
LCD_BRD_TOUCH_INT: J38.29 ; also on sheet 20
LCD_BRD_TOUCH_RESETn: R686.1 U110.11(P11) U113.1(A)
LCD_DISPLAY_EN: J38.30 R687.2 U110.10(P10)
LCD_SHIELD: FL15.2 J38.SH1 J38.SH2 J38.SH3 J38.SH4
LCD_TOUCH_RESETn: J38.39 R698.1 U113.4(Y)
LED1: LD11.1 U84.3(DRAIN0)
LED2: LD12.1 U84.4(DRAIN1)
LED3: LD13.1 U84.5(DRAIN2)
LED4: LD14.1 U84.6(DRAIN3)
LED5: LD10.1 U84.11(DRAIN4)
LED6: LD15.1 U84.12(DRAIN5)
LED7: LD9.1 U84.13(DRAIN6)
LED8: LD8.1 U84.14(DRAIN7)
MAIN_UART1_SEL: U110.15(P15) ; also on sheet 31
MCU_BOOTMODE0: R225.2 ; also on sheet 25 34
MCU_BOOTMODE1: R548.2 ; also on sheet 25 34
MCU_CLKOUT: R185.2 R190.1 U32.13(PRI_INP) ; also on sheet 34
MCU_ETH1_INTn: U96.5(A1) ; also on sheet 23
MCU_ETH1_INTn_SDIO: R600.1 U96.8(B1) ; also on sheet 18
MCU_RGMII1_CLKIN: R203.2 ; also on sheet 23
MCU_UART_SEL: U109.5(B1) ; also on sheet 31
MCU_UART_SEL_IO_EXP: U109.8(A1) U110.16(P16)
OLDI0_A0N: J38.8 R599.2 U34.J28(OLDI0_A0N)
OLDI0_A0P: J38.9 R599.1 U34.K28(OLDI0_A0P)
OLDI0_A1N: J38.11 R597.2 U34.L27(OLDI0_A1N)
OLDI0_A1P: J38.12 R597.1 U34.K27(OLDI0_A1P)
OLDI0_A2N: J38.14 R595.2 U34.K24(OLDI0_A2N)
OLDI0_A2P: J38.15 R595.1 U34.J24(OLDI0_A2P)
OLDI0_A3N: J38.17 R594.2 U34.J26(OLDI0_A3N)
OLDI0_A3P: J38.18 R594.1 U34.K26(OLDI0_A3P)
OLDI0_CLKN: J38.20 R598.2 U34.L25(OLDI0_CLKN)
OLDI0_CLKP: J38.21 R598.1 U34.K25(OLDI0_CLKP)
OSPI_LBCLKO_GPIO: R705.2 ; also on sheet 19
PCIe0_PRSNTn: J5.21 ; also on sheet 20
PCIE1_ATEST: TP51.1(TP) U34.AC13(PCIE1ATEST)
PCIe1_PRSNTn: J5.22 ; also on sheet 20
PCIe1_RESREF: R497.1 U34.AC14(PCIE1REFRES)
PCIE1_SGMII1_RXN1: J5.52 U34.AG9(PCIE1_RXN0)
PCIE1_SGMII1_RXP1: J5.53 U34.AH10(PCIE1_RXP0)
PCIE1_SGMII1_TXN1: C58.2 J5.50
PCIE1_SGMII1_TXN1_C: C58.1 U34.AH9(PCIE1_TXN0)
PCIE1_SGMII1_TXP1: C59.2 J5.49
PCIE1_SGMII1_TXP1_C: C59.1 U34.AG8(PCIE1_TXP0)
PCIe_GPIO_RESET_IN: J5.12 R705.1 R743.1
PORz_OUT: J5.30 U113.2(B) ; also on sheet 18 19 21 25 33 34 44
PRG0_RGMII1_ETH1_CLK: R204.2 ; also on sheet 33
PRG0_RGMII2_ETH2_CLK: R205.2 ; also on sheet 33
PRG1_RGMII1_ETH1_CLK: R206.2 ; also on sheet 33
PRG1_RGMII2_ETH2_CLK: R207.2 ; also on sheet 33
PRG2_ETH_LED0: R464.2 R737.2 ; also on sheet 20
PRG2_ETH_LED1: R458.2 R738.2 ; also on sheet 20
PRG2_MDC: J5.16 ; also on sheet 21 22 29
PRG2_MDIO: J5.15 ; also on sheet 21 22 29
PRG2_RGMII1_ETH1_CLK: R170.2 ; also on sheet 21
PRG2_RGMII2_ETH2_CLK: R169.2 ; also on sheet 22
PRG2_RGMII_INTn: U45.5(A1) ; also on sheet 21 22
PRG2_RGMII_INTn_3V3: R270.1 U45.8(B1) ; also on sheet 34
PRI_INN: C145.1 R172.1 R173.2 U32.14(PRI_INN)
REFCLK0N: J5.58 R60.1 R725.1
REFCLK0N_R: R725.2 U34.AF9(REFCLK0N)
REFCLK0P: J5.59 R59.1 R724.1
REFCLK0P_R: R724.2 U34.AF10(REFCLK0P)
REFCLK1N: J5.27 R40.1 R727.1
REFCLK1N_R: R727.2 U34.AE8(REFCLK1N)
REFCLK1P: J5.28 R39.1 R726.1
REFCLK1P_R: R726.2 U34.AE9(REFCLK1P)
RESET_SoC_MPU: U110.12(P12) ; also on sheet 41
SERDES_BRD_DET: J5.45 ; also on sheet 20
SOC_I2C0_SCL: J33.3 U84.15(SCL) U110.19(SCL) ; also on sheet 11 33 34
SOC_I2C0_SDA: J33.2 U84.2(SDA) U110.20(SDA) ; also on sheet 11 33 34
SOC_I2C1_SCL: J38.26 ; also on sheet 34
SOC_I2C1_SDA: J38.27 ; also on sheet 34
SOC_MCU_SCL: J5.2 ; also on sheet 20 34 44
SOC_MCU_SDA: J5.3 ; also on sheet 20 34 44
SoC_PORz: R743.2 ; also on sheet 34 39
SOC_SERDES_REFCLK0_N: J5.24 ; also on sheet 30
SOC_SERDES_REFCLK0_P: J5.25 ; also on sheet 30
SOC_SERDES_REFCLK1_N: J5.55 U34.AH6(PCIE1_REFCLKN)
SOC_SERDES_REFCLK1_P: J5.56 U34.AH7(PCIE1_REFCLKP)
SOC_SPI1_CLK: J20.4 J38.32 ; also on sheet 34 44
SOC_SPI1_CS: J20.3 R316.1 R317.1
SOC_SPI1_CS0: R317.2 R675.1 ; also on sheet 34
SOC_SPI1_CS1: R316.2 ; also on sheet 34 44
SOC_SPI1_MISO: J20.2 J38.36 ; also on sheet 34 44
SOC_SPI1_MOSI: J20.1 J38.35 ; also on sheet 34 44
SOC_WKUP_SCL: J5.33 J38.23 ; also on sheet 20 33 34 41 44
SOC_WKUP_SDA: J5.34 J38.24 ; also on sheet 20 33 34 41 44
SOC_WKUP_UART0_RTS_3V3: J11.2 ; also on sheet 31 34
SOC_WKUP_UART0_TX_3V3: J11.5 ; also on sheet 31 34
TCA9555_EXP_INT: R661.1 U110.22(~{INT})
TIMER_IO0: J19.1 ; also on sheet 34
TIMER_IO1: J19.2 ; also on sheet 34
TIMER_IO2: J19.3 ; also on sheet 44
TIMER_IO3: J19.4 ; also on sheet 44
TIMER_IO6: J19.5 ; also on sheet 44
TIMER_IO7: J19.6 ; also on sheet 44
USB0_DM: J5.36 ; also on sheet 30
USB0_DP: J5.37 ; also on sheet 30
USB0_DRV_VBUS: J5.5 ; also on sheet 30
USB0_ID_SOC: J5.14 ; also on sheet 30
USB0_PCIE0_SGMII0_RXN0: J5.40 ; also on sheet 30
USB0_PCIE0_SGMII0_RXP0: J5.39 ; also on sheet 30
USB0_PCIE0_SGMII0_TXN0: J5.43 ; also on sheet 30
USB0_PCIE0_SGMII0_TXP0: J5.42 ; also on sheet 30
USB0_VBUS: C691.1 J5.47 ; also on sheet 30
WKUP_OSC0_XIN: R448.2 ; also on sheet 11 34
WKUP_UART_SEL: U110.14(P14) ; also on sheet 31
N16248811: R448.1 U32.20(Y7)
N16248833: R169.1 U32.18(Y6)
N16248855: R170.1 U32.17(Y5)
N16248877: R207.1 U32.8(Y4)
N16248899: R206.1 U32.7(Y3)
N16248921: R205.1 U32.5(Y2)
N16248943: R204.1 U32.3(Y1)
N16248965: R203.1 U32.1(Y0)
N17247526: LD11.2 R107.2
N17247539: LD12.2 R108.2
N17247599: LD13.2 R109.2
N17247637: LD14.2 R110.2
N17247662: LD10.2 R106.2
N17247701: LD15.2 R105.2
N17247743: LD9.2 R104.2
N17247786: LD8.2 R103.2
N17248427: R431.2 U84.7(A2)
N17248432: R453.2 U84.10(A1)
N17248439: R454.2 U84.9(A0)
N18184841: R667.1 U110.18(A0)
N18184861: R660.2 U110.23(A1)
N18184865: R659.2 U110.24(A2)
N18320293: C161.2 R192.1 R194.1 Y1.2
N18320301: C156.2 R191.1 R192.2 Y1.1
N18321769: R199.1 U32.31(OE)
N18436285: LD18.1(CATHODE1) Q17.3(D)
N18436298: LD18.3(ANODE) R224.1
N18436321: Q6.1(G) R225.1
N18436342: LD18.2(CATHODE2) Q6.3(D)
N18436344: Q17.1(G) R548.1
N18436628: Q11.1(G) R464.1
N18436656: LD17.2 R177.1
N18436666: LD17.1 Q11.3(D)
N18436681: Q10.1(G) R458.1
N18436707: LD16.2 R155.1
N18860929: R672.1 U109.10(DIR1)
N18860951: R673.1 U109.2(~{OE})
N20141585: R680.1 U109.1(DIR2)
N20155231: R246.1 U45.6(OE)
N20155262: R604.1 U96.6(OE)
N21124530: J38.33 R675.2
N21870672: LD16.1 Q10.3(D)

Not connected (* = marked no-connect by the designer): J5 31*; J11 3*; J30 3*; U32 22(Y8)* 24(Y9)* 27(SEC_INN)* 28(SEC_INP)*; U45 1(B2)* 4(A2)*; U96 1(B2)* 4(A2)*; U110 17(P17)*

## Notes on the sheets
sheet 35
- SERDES INTERFACE
- SERDES CONNECTOR
- SERDES POWER CONNECTOR
- OLDI INTERFACE
sheet 36
- ETHERNET PHY  CLOCK BUFFER
- REFERENCE INPUT SELECTION
sheet 37
- ETHERNET LED's
- I2C ADDRESS: 0x60
- I2C IO Expander
- PRG2 ETHERNET LED's
- I2C ADDRESS: 0x21
sheet 38
- TEST HEADER
- SPI TEST HEADER
- I2C TEST HEADER
- 3V3  IO level
- 3V3 IO level
- D0
- D1
- SCL
- CS
- SDA
- SCLK
- GND
- GND
- UART  TEST HEADER
- TIMER SIGNALS  TEST HEADER
- 3.3V IO level
- MCU UART
- WKUP UART
- 3V3 IO Level
- 3V3 IO level
- CTS
- CTS
- TXD
- TXD
- RXD
- RXD
- NC
- NC
- GND
- RTS
- GND
- RTS
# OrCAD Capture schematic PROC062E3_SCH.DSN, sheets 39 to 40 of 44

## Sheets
39 39. VOLTAGE SUPERVISOR: size C; title: VOLTAGE SUPERVISOR & WKUP LEDs
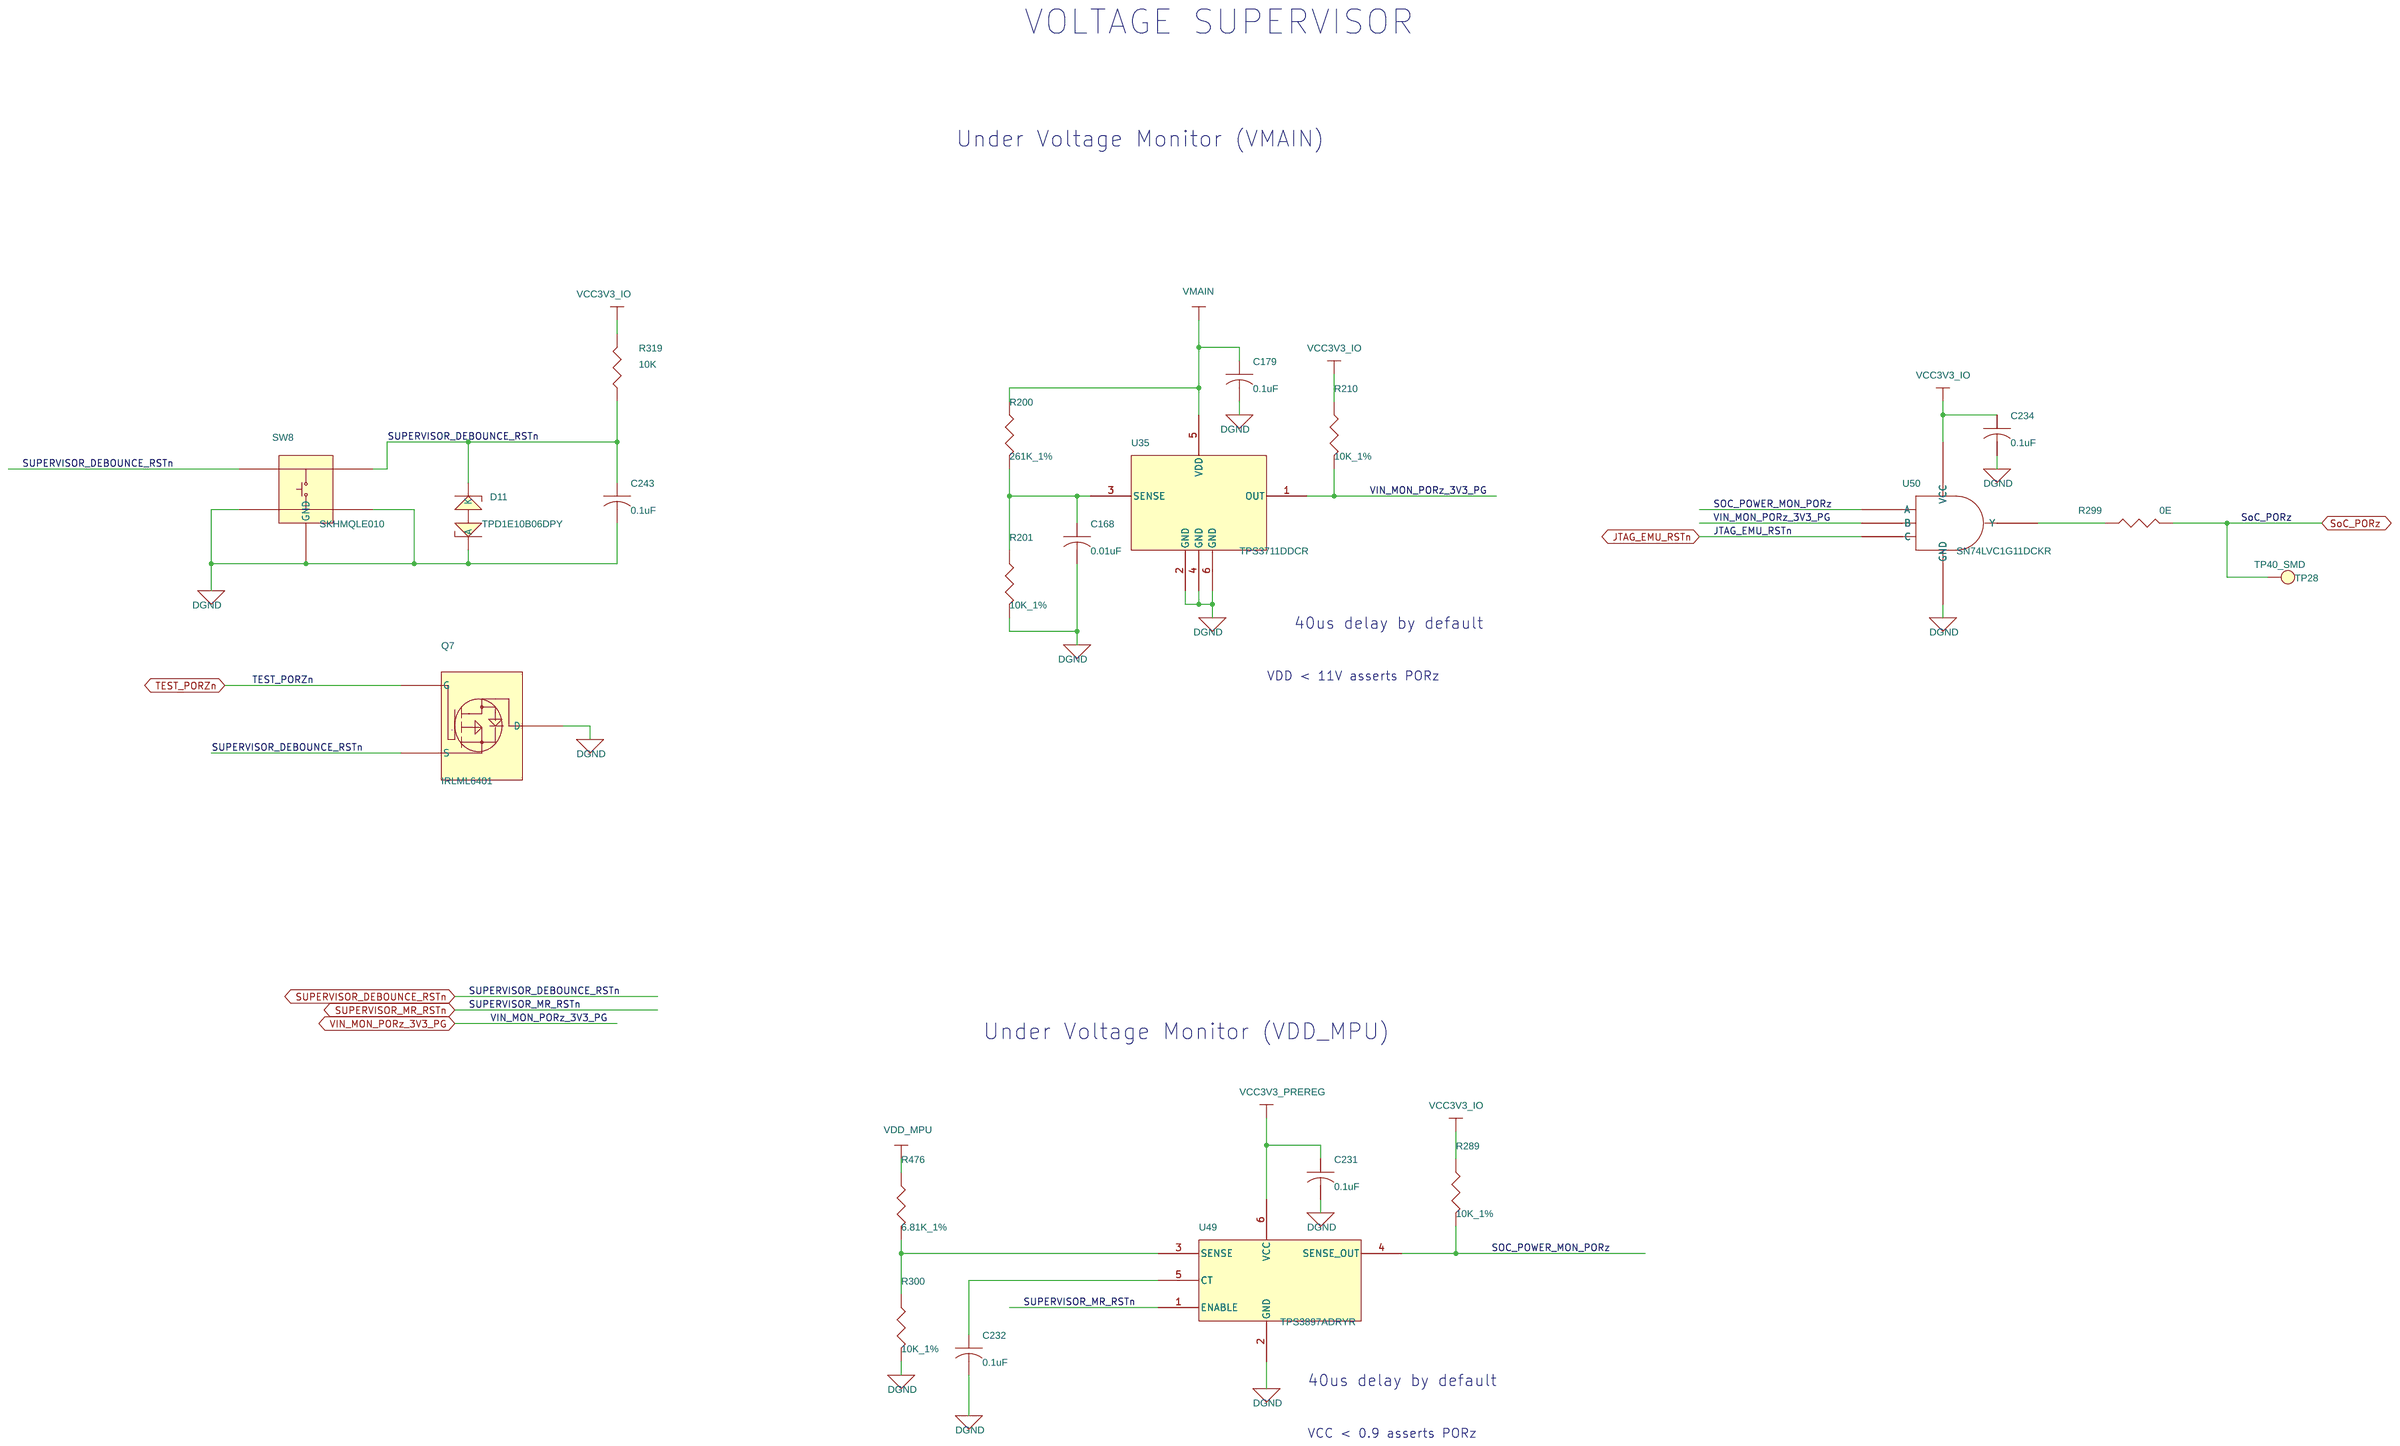
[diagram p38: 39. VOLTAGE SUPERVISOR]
40 40. PRE_REG&SERDES POWER SUPPLY: size C; title: PRE_REG and SERDES POWER SUPPLY

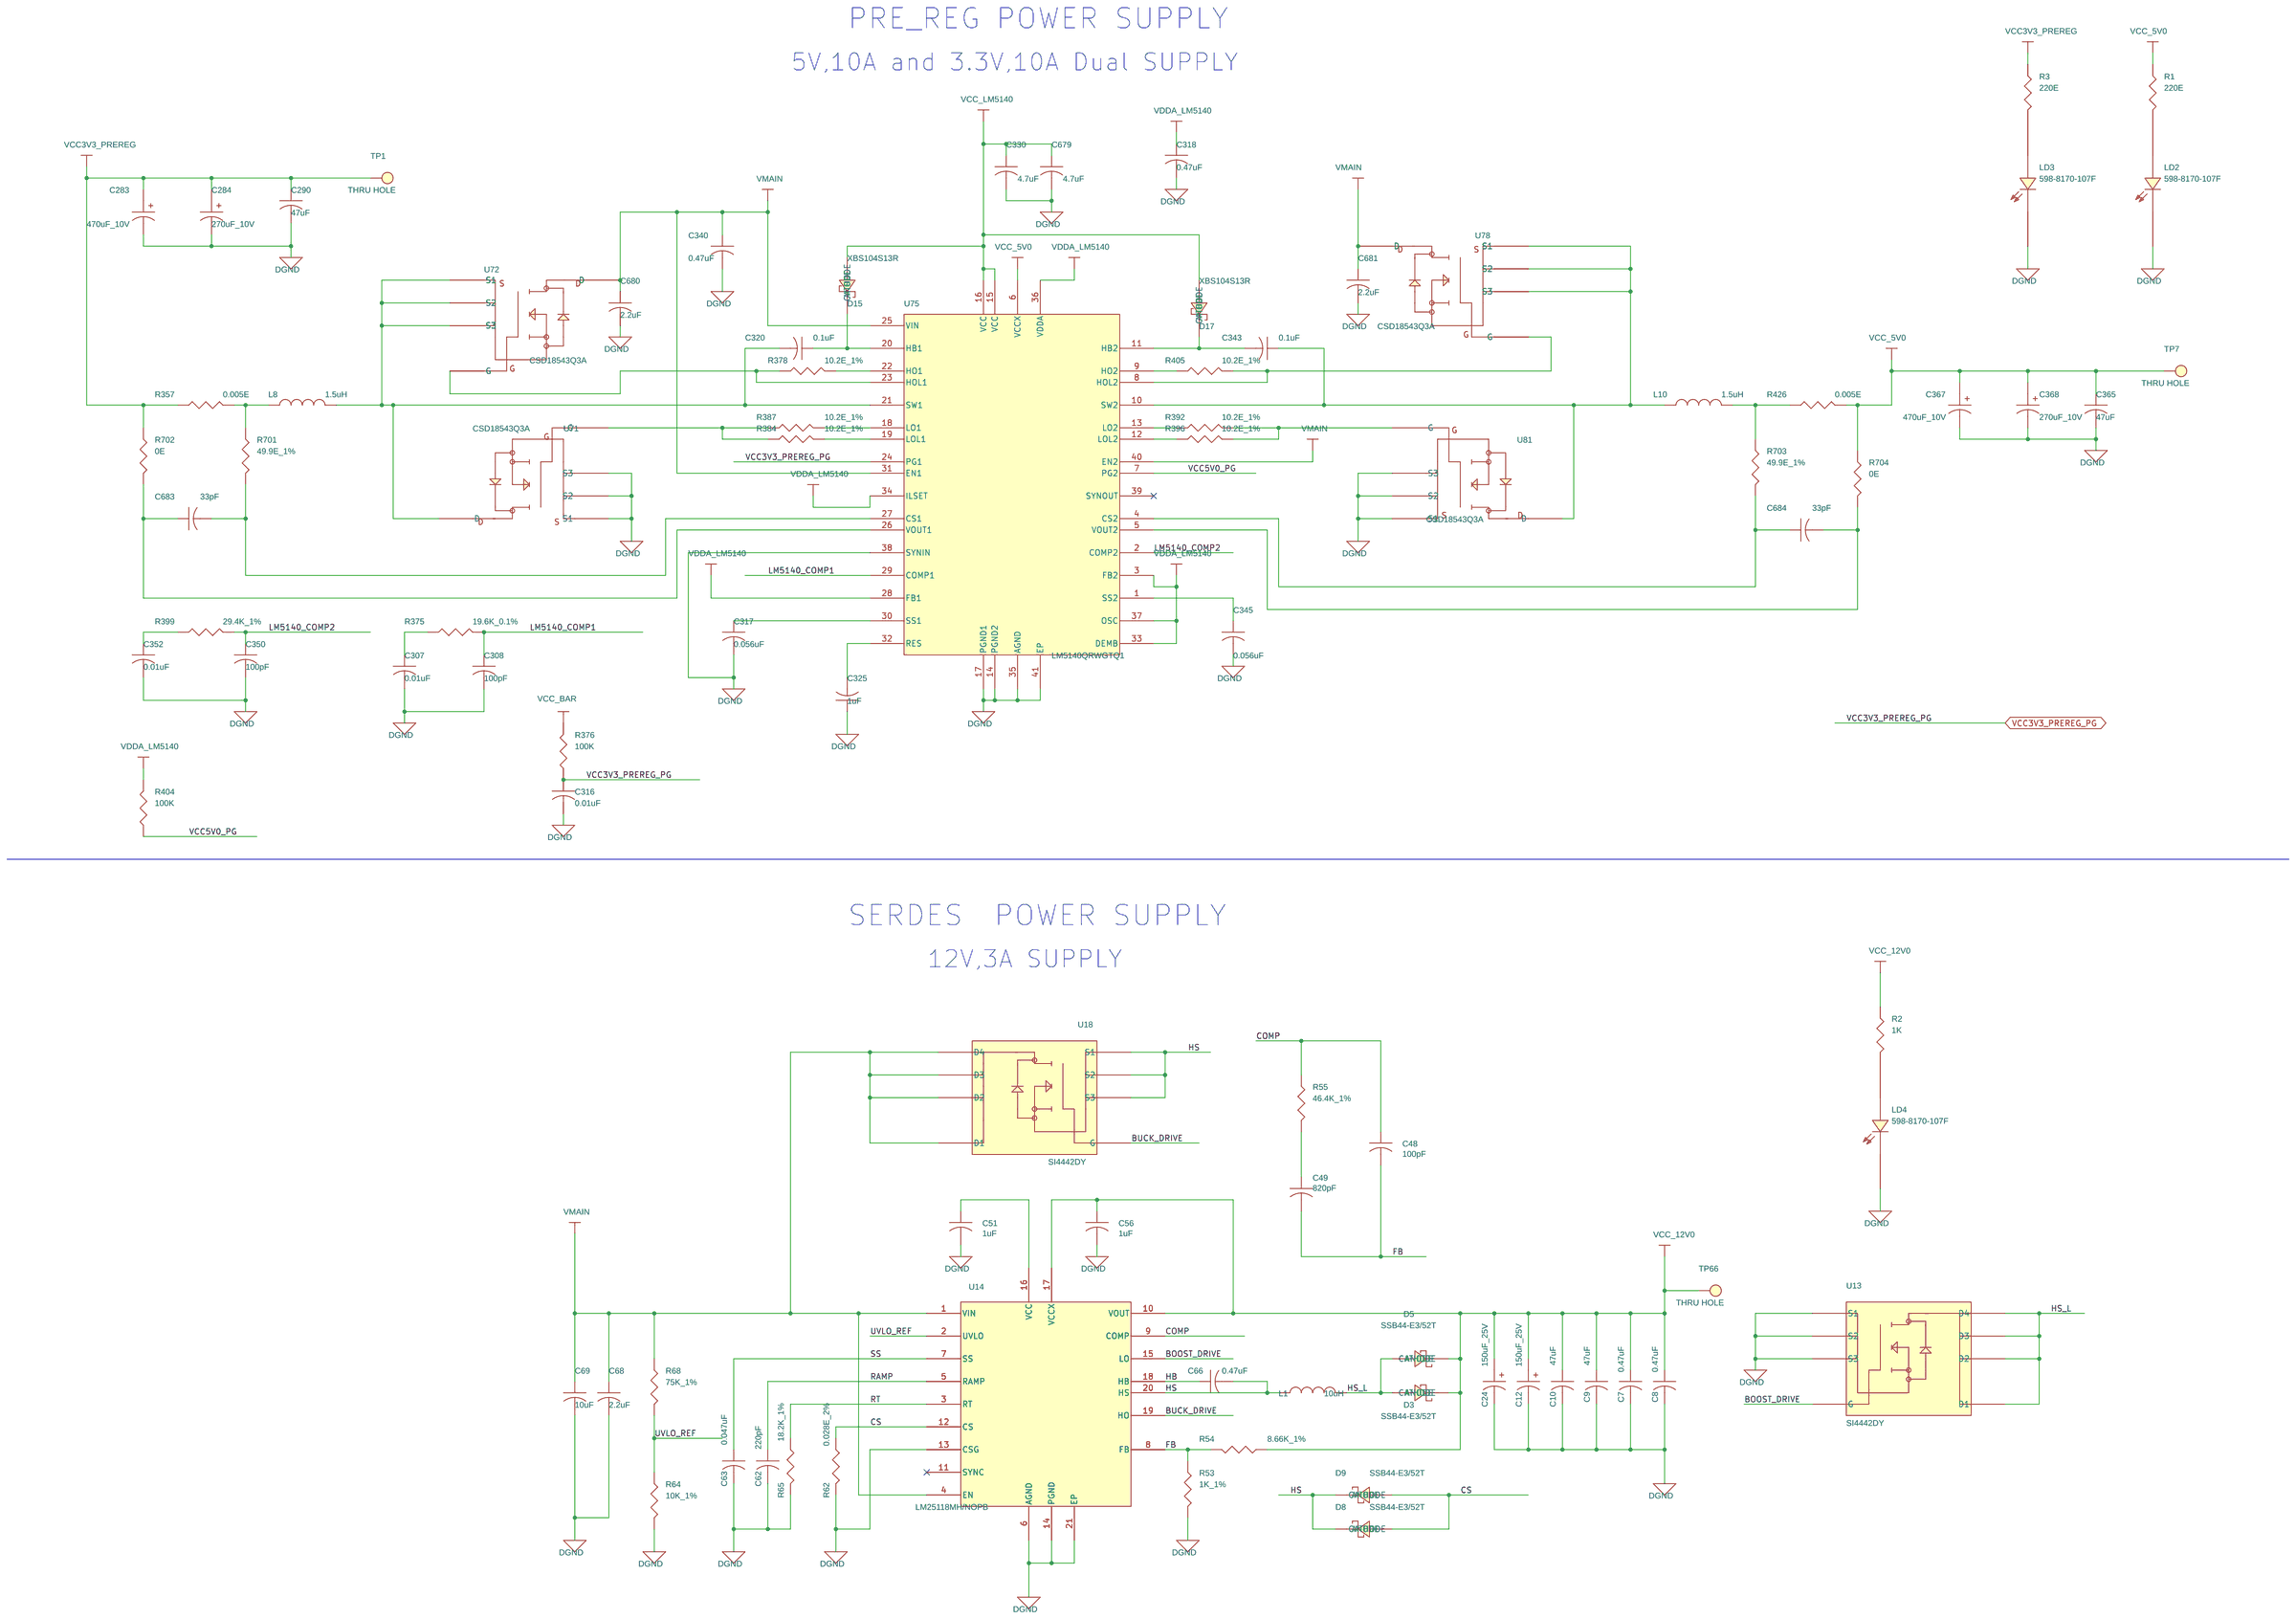
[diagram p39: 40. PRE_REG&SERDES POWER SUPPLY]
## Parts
sheet 39. VOLTAGE SUPERVISOR
C168  0.01uF  [CAP0201_0-5]
C179  0.1uF  [CAP0603_1]
C231  0.1uF  [CAP0201_0-5]
C232  0.1uF  [CAP0201_0-5]
C234  0.1uF  [CAP0201_0-5]
C243  0.1uF  [CAP0201_0-5]
D11  TPD1E10B06DPY  [DIO_DFN0402]
Q7  IRLML6401  [TO_SOT23-123]
R200  261K_1%  [RES0402_0-5]
R201  10K_1%  [RES0402_0-5]
R210  10K_1%  [RES0402_0-5]
R289  10K_1%  [RES0402_0-5]
R299  0E  [RES0402_0-5]
R300  10K_1%  [RES0402_0-5]
R319  10K  [RES0402_0-5]
R476  6.81K_1%  [RES0402_0-5]
SW8  SKHMQLE010  [SW4_SKHMQLE010_240X260_SMD_3-1]
TP28  TP40_SMD  [TP40_SMD]
U35  TPS3711DDCR  [SOT23-6_1-1]
U49  TPS3897ADRYR  [SON6_19-68_40X60_0-6]
U50  SN74LVC1G11DCKR  [SC70-6]
sheet 40. PRE_REG&SERDES POWER SUPPLY
C7  0.47uF  [CAP0805_1]
C8  0.47uF  [CAP0805_1]
C9  47uF  [CAP1206_2]
C10  47uF  [CAP1206_2]
C12  150uF_25V  [CAPAE_CASE8383_11]
C24  150uF_25V  [CAPAE_CASE8383_11]
C48  100pF  [CAP0402]
C49  820pF  [CAP0402_0-75]
C51  1uF  [CAP0603_1]
C56  1uF  [CAP0603_1]
C62  220pF  [CAP0402]
C63  0.047uF  [CAP0402_0-75]
C66  0.47uF  [CAP0805_1]
C68  2.2uF  [CAP0805_1]
C69  10uF  [CAP1206_2]
C283  470uF_10V  [CAPAE_D8CASE_8]
C284  270uF_10V  [CAP_87510524_270X270_SMD_7-7]
C290  47uF  [CAP1206_2]
C307  0.01uF  [CAP0402_0-75]
C308  100pF  [CAP0402]
C316  0.01uF  [CAP0201_0-5]
C317  0.056uF  [CAP0402_0-75]
C318  0.47uF  [CAP0603_1]
C320  0.1uF  [CAP0201_0-5]
C325  1uF  [CAP0402_0-75]
C330  4.7uF  [CAP0402_0-75]
C340  0.47uF  [CAP0805_1-5]
C343  0.1uF  [CAP0201_0-5]
C345  0.056uF  [CAP0402_0-75]
C350  100pF  [CAP0402]
C352  0.01uF  [CAP0402_0-75]
C365  47uF  [CAP1206_2]
C367  470uF_10V  [CAPAE_D8CASE_8]
C368  270uF_10V  [CAP_87510524_270X270_SMD_7-7]
C679  4.7uF  [CAP0402_0-75]
C680  2.2uF  [CAP0805_1]
C681  2.2uF  [CAP0805_1]
C683  33pF  [CAP0201_0-5]
C684  33pF  [CAP0201_0-5]
D3  SSB44-E3/52T  [DIO_SMB_2-5]
D5  SSB44-E3/52T  [DIO_SMB_2-5]
D8  SSB44-E3/52T  [DIO_SMB_2-5]
D9  SSB44-E3/52T  [DIO_SMB_2-5]
D15  XBS104S13R  [DIO_SOD323_1]
D17  XBS104S13R  [DIO_SOD323_1]
L1  10uH  [IND_ETQP5MYFM_310X290_SMD_5-4]
L8  1.5uH  [IND_ETQP4MKVK_350X330_SMD_4]
L10  1.5uH  [IND_ETQP4MKVK_350X330_SMD_4]
LD2  598-8170-107F  [LED_0805_0-7]
LD3  598-8170-107F  [LED_0805_0-7]
LD4  598-8170-107F  [LED_0805_0-7]
R1  220E  [RES0402_0-5]
R2  1K  [RES0201]
R3  220E  [RES0402_0-5]
R53  1K_1%  [RES0402_0-5]
R54  8.66K_1%  [RES0402]
R55  46.4K_1%  [RES0402]
R62  0.028E_2%  [RES0815_0-75]
R64  10K_1%  [RES0402_0-5]
R65  18.2K_1%  [RES0402]
R68  75K_1%  [RES0402_0-5]
R357  0.005E  [RES1206]
R375  19.6K_0.1%  [RES0402]
R376  100K  [RES0402_0-5]
R378  10.2E_1%  [RES0402_0-5]
R384  10.2E_1%  [RES0402_0-5]
R387  10.2E_1%  [RES0402_0-5]
R392  10.2E_1%  [RES0402_0-5]
R396  10.2E_1%  [RES0402_0-5]
R399  29.4K_1%  [RES0402]
R404  100K  [RES0402_0-5]
R405  10.2E_1%  [RES0402_0-5]
R426  0.005E  [RES1206]
R701  49.9E_1%  [RES0201]
R702  0E  [RES0402_0-5]
R703  49.9E_1%  [RES0201]
R704  0E  [RES0402_0-5]
TP1  THRU HOLE  [TP_40X65]
TP7  THRU HOLE  [TP_40X65]
TP66  THRU HOLE  [TP_40X65]
U13  SI4442DY  [SOIC8_1-8]
U14  LM25118MH/NOPB  [ETSSOP20_25-59_260X180_1-1]
U18  SI4442DY  [SOIC8_1-8]
U71  CSD18543Q3A  [VSONP8_CSD18543Q_120X130_0-9]
U72  CSD18543Q3A  [VSONP8_CSD18543Q_120X130_0-9]
U75  LM5140QRWGTQ1  [QFN40_19-68_240X240_0-9]
U78  CSD18543Q3A  [VSONP8_CSD18543Q_120X130_0-9]
U81  CSD18543Q3A  [VSONP8_CSD18543Q_120X130_0-9]

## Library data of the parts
C168 C316 = CAP: CAP CERAMIC 0.01uF 25V 10% X5R 0201; Chkd/date: MANIRAJA/230118; Crtd /date: MANIRAJA/230118; Custom_Duty: 15%; Customs_HS_Code: 85322990; Distributor_name: DIGIKEY; Distributor_part_number: GRM033R61E103KA12J-ND; Height: 0.33MM; Mfr_name: MURATA; Mfr_part_number: GRM033R61E103KA12J; Mistral Part No: 120018010007-R; Package: 0201; Part_type: CAPACITORS\CERAMIC; Project: TI_MAXIE_CPB; RoHS: RoHS; Temperature: -55°C+85°C; Tolerance: 10%; Voltage: 25V; Wattage: NA; Weight: 0.33mg; Datasheet: Y:\MIS_DATABASE\DATASHEETS\CAPACITORS\GRM033R61E103KA12.PDF
C179 = CAP: CAP CERAMIC 0.1uF 50V 20% X7R 0603; Chkd/date: MANIRAJA/240118; Crtd /date: MANIRAJA/240118; Custom_Duty: 15%; Customs_HS_Code: 85322990; Distributor_name: DIGIKEY; Distributor_part_number: 399-7845-1-ND; Height: 0.95MM; Mfr_name: KEMET; Mfr_part_number: C0603C104M5RACTU; Mistral Part No: 120018010021-R; Package: 0603; Part_type: CAPACITORS\CERAMIC; Project: TI_MAXIE_CPB; RoHS: RoHS; Temperature: -55°C+125°C; Tolerance: 20%; Voltage: 50V; Wattage: NA; Weight: 2mg; Datasheet: Y:\MIS_DATABASE\DATASHEETS\CAPACITORS\KEMET-X7R-SER.PDF
C231 C232 C234 C243 C320 C343 = CAP: CAP CERAMIC 0.1uF 16V 10% X5R 0201; Chkd/date: MANIRAJA/120218; Crtd /date: MANIRAJA/120218; Custom_Duty: 15%; Customs_HS_Code: 85322990; Distributor_name: DIGIKEY; Distributor_part_number: 490-16742-1-ND; Height: 0.33MM; Mfr_name: MURATA; Mfr_part_number: GRM033R61C104KE84J; Mistral Part No: 120009030072-R; Package: 0201; Part_type: CAPACITORS\CERAMIC; Project: TI_MAXIE_CPB; RoHS: RoHS; Temperature: -55°C+85°C; Tolerance: 10%; Voltage: 16V; Wattage: NA; Weight: 0.33mg; Datasheet: Y:\MIS_DATABASE\DATASHEETS\CAPACITORS\GRM033R61C104KE84.PDF
D11 = DIODE_PESD: DIODE 1CH ESD PROTECTION SMD(0402); Chkd/date: USMAN/021214; Crtd /date: VASANTHA/181114; Custom_Duty: 15%; Customs_HS_Code: 85423100; Distributor_name: DIGIKEY; Distributor_part_number: 296-30406-1-ND; Height: 0.45MM; Mfr_name: TEXAS INSTRUMENTS; Mistral Part No: 130014110022-R; Package: SMD; Part_type: DIODE\MISC; Project: GALILEO_EVM; RoHS: RoHS; Temperature: -40°C+125°C; Tolerance: NA; Voltage: NA; Wattage: NA; Weight: NA; Datasheet: Y:\MIS_DATABASE\DATASHEETS\ICS\INTERFACE\TPD1E10B06.PDF
Q7 = MOSFET_IRLML6401TR: TRANSISTOR MOSFET P-CHANNEL SOT23-3; Chkd/date: SHREESHAIL/020206; Crtd /date: MAZHAR/040505; Custom_Duty: 15%; Customs_HS_Code: 85412900; Distributor_name: DIGIKEY; Distributor_part_number: IRLML6401PBFCT-ND; Height: 1.11MM; Mfr_name: IRF; Mfr_part_number: IRLML6401TRPBF; Mistral Part No: 130009031213-P; Package: SOT23-3; Part_type: TRANSISTOR\MOSFET; Project: G4_SVGA; Remarks: Part# replaced from “IRLML6401TR” to “IRLML6401TRPBF” making as a Pb-free part. (BAVISH/220311).; RoHS: Pb-Free; Temperature: -55°C+150°C; Tolerance: NA; Voltage: NA; Wattage: NA; Weight: NA; Datasheet: Y:\MIS_DATABASE\DATASHEETS\DISCRETES\TRANSISTORS_FETS\IRLML6401.PDF
R200 = RESISTOR: RES 261K 1/16W 1% 0402; Chkd/date: MANIRAJA/101017; Crtd /date: JEBRAN/250815; Custom_Duty: 15%; Customs_HS_Code: 85332119; Distributor_name: DIGIKEY; Distributor_part_number: 311-261KLRCT-ND; Height: 0.40MM; Mfr_name: YAGEO AMERICA; Mfr_part_number: RC0402FR-07261KL; Mistral Part No: 110015080042-R; Package: 0402; Part_type: RESISTORS\FIXED; Project: OCTBTS3600; RoHS: RoHS; Temperature: -55°C+155°C; Tolerance: 1%; Voltage: NA; Wattage: 1/16W; Weight: 0.65mg; Datasheet: Y:\MIS_DATABASE\DATASHEETS\RESISTORS\YAGEO.PDF
R64 R201 R210 R289 R300 = RESISTOR: RES 10K 1/16W 1% 0402; Chkd/date: VASANTHA/201216; Crtd /date: GEETHA/290506; Custom_Duty: 15%; Customs_HS_Code: 85332119; Distributor_name: DIGIKEY; Distributor_part_number: 311-10.0KLRTR-ND; Footprint Path: Y:\MIS_DATABASE\Library\ALTIUM_TOOL\PCB_FOOTPRINTS\Altium_Footprint_Lib.PcbLib; Height: 0.40MM; Library Path: Y:\MIS_DATABASE\Library\ALTIUM_TOOL\SCHEMATICS_PARTS\MS_DISCRETE_Library.schlib; Mfr_name: YAGEO AMERICA; Mfr_part_number: RC0402FR-0710KL; Mistral Part No: 110009030220-P; Package: 0402; Part_type: RESISTORS\FIXED; Project: VOCERA; RoHS: Pb-Free; Temperature: -55°C+155°C; Tolerance: 1%; Voltage: NA; Wattage: 1/16W; Weight: 0.65mg; Datasheet: Y:\MIS_DATABASE\DATASHEETS\RESISTORS\YAGEO-RC0402.PDF
R299 R702 R704 = RESISTOR: RES 0E 1/16W 0402; Chkd/date: VASANTHA/201216; Crtd /date: MUDDU/190810; Custom_Duty: 15%; Customs_HS_Code: 85332119; Distributor_name: DIGIKEY; Distributor_part_number: 541-0.0JCT-ND; Footprint Path: Y:\MIS_DATABASE\Library\ALTIUM_TOOL\PCB_FOOTPRINTS\Altium_Footprint_Lib.PcbLib; Height: 0.40MM; Library Path: Y:\MIS_DATABASE\Library\ALTIUM_TOOL\SCHEMATICS_PARTS\MS_DISCRETE_Library.schlib; Mfr_name: VISHAY; Mfr_part_number: CRCW04020000Z0ED; Mistral Part No: 110010080019-P; Package: 0402; Part_type: RESISTORS\FIXED; Project: PB_BUGBASE; RoHS: Pb-Free; Temperature: -55°C+155°C; Tolerance: NA; Voltage: NA; Wattage: 1/16W; Weight: 0.65g/1000pcs; Datasheet: Y:\MIS_DATABASE\DATASHEETS\RESISTORS\CRCW0603.PDF
R319 = RESISTOR: RES 10K 1/16W 5% 0402; Chkd/date: VASANTHA/061216; Crtd /date: MAZHAR/230805; Custom_Duty: 15%; Customs_HS_Code: 85332119; Distributor_name: DIGIKEY; Distributor_part_number: 311-10KJRCT-ND; Footprint Path: Y:\MIS_DATABASE\Library\ALTIUM_TOOL\PCB_FOOTPRINTS\Altium_Footprint_Lib.PcbLib; Height: 0.40MM; Library Path: Y:\MIS_DATABASE\Library\ALTIUM_TOOL\SCHEMATICS_PARTS\MS_DISCRETE_Library.schlib; Mfr_name: YAGEO AMERICA; Mfr_part_number: RC0402JR-0710KL; Mistral Part No: 110009030208-R; Package: 0402; Part_type: RESISTORS\FIXED; Project: HSE; RoHS: Pb-Free; Temperature: -55°C+155°C; Tolerance: 5%; Voltage: NA; Wattage: 1/16W; Weight: 0.65mg; Datasheet: Y:\MIS_DATABASE\DATASHEETS\RESISTORS\YAGEO-RC0402.PDF
R476 = RESISTOR: RES 6.81K 1/16W 1% 0402; Chkd/date: VASANTHA/181017; Crtd /date: VASANTHA/181017; Custom_Duty: 15%; Customs_HS_Code: 85332119; Distributor_name: DIGIKEY; Distributor_part_number: 311-6.81KLRCT-ND; Height: 0.40MM; Mfr_name: YAGEO AMERICA; Mfr_part_number: RC0402FR-076K81L; Mistral Part No: 110017100003-R; Package: 0402; Part_type: RESISTORS\FIXED; Project: TI_MAXIE_CPB; RoHS: RoHS; Temperature: -55°C+155°C; Tolerance: 1%; Voltage: NA; Wattage: 1/16W; Weight: NA; Datasheet: Y:\MIS_DATABASE\DATASHEETS\RESISTORS\YAGEO-RC0402.PDF
SW8 = SW4_SKHUPLE010: SWITCH TACTILE SPST ST SMD; Chkd/date: MANIRAJA/051017; Crtd /date: MANIRAJA/051017; Custom_Duty: 24%; Customs_HS_Code: 85369090; Distributor_name: MOUSER; Distributor_part_number: 688-SKHMQLE010; Height: 3.10MM; Mfr_name: ALPS; Mistral Part No: 130017100007-R; Package: SMD; Part_type: ELECTRO-MECHANICAL\SWITCH; Project: TI_MAXIE_CPB; RoHS: RoHS; Temperature: -30°C+85°C; Tolerance: NA; Voltage: NA; Wattage: NA; Weight: NA; Datasheet: Y:\MIS_DATABASE\DATASHEETS\MISC\SWITCHES\SKHMQLE010.PDF
TP28 = TESTPOINT: TESTPOINT CIR 40 SMD; Chkd/date: MAZHAR/190505; Crtd /date: MAZHAR/190505; Distributor_name: NA; Distributor_part_number: NA; Footprint Path: Y:\MIS_DATABASE\Library\ALTIUM_TOOL\PCB_FOOTPRINTS\Altium_Footprint_Lib.PcbLib; Height: NA; Library Path: Y:\MIS_DATABASE\Library\ALTIUM_TOOL\SCHEMATICS_PARTS\MS_DISCRETE_Library.schlib; MECHANICAL 3D STEP FILE: NA; Mfr_name: LOCAL; Mistral Part No: 130009030933; Package: SMD; Project: RAINIER-3; RoHS: NA; Temperature: NA; Tolerance: NA; Voltage: NA; Wattage: NA; Weight: NA; Datasheet: NA
U35 = TPS3711DDCR_SOT23-6: IC 36V VOLTAGE DETECTOR SOT23-6; Chkd/date: MANIRAJA/091017; Crtd /date: MANIRAJA/091017; Custom_Duty: 15%; Customs_HS_Code: 85423100; Distributor_name: DIGIKEY; Distributor_part_number: 296-43278-1-ND; Height: 1.10MM; Mfr_name: TEXAS INSTRUMENTS; Mistral Part No: 142017100008-R; Package: SOT23-6; Part_type: ICS\POWER\MANAGEMENT; Project: TI_MAXIE_CPB; RoHS: RoHS; Temperature: -40°C+125°C; Tolerance: NA; Voltage: NA; Wattage: NA; Weight: 30mg; Datasheet: Y:\MIS_DATABASE\DATASHEETS\ICS\POWER\TPS3711D.PDF
U49 = TPS3897ADRYR_SON6: IC 1-CH ADJ VOLTAGE MONITOR SON6; Chkd/date: MANIRAJA/091017; Crtd /date: MANIRAJA/091017; Custom_Duty: 15%; Customs_HS_Code: 85423100; Distributor_name: DIGIKEY; Distributor_part_number: 296-29810-1-ND; Height: 0.60MM; Mfr_name: TEXAS INSTRUMENTS; Mistral Part No: 142017100007-R; Package: SON6; Part_type: ICS\POWER\MANAGEMENT; Project: TI_MAXIE_CPB; RoHS: RoHS; Temperature: -40°C+125°C; Tolerance: NA; Voltage: NA; Wattage: NA; Weight: NA; Datasheet: Y:\MIS_DATABASE\DATASHEETS\ICS\POWER\TPS389X.PDF
U50 = SN74LVC1G11DCKR_SC70-6: IC SINGLE 3-INPUT POSITIVE-AND GATE SC70-6; Chkd/date: SHREESHAIL/220506; Crtd /date: MAZHAR/150506; Custom_Duty: 15%; Customs_HS_Code: 85423100; Distributor_name: DIGIKEY; Distributor_part_number: 296-18066-1-ND; Height: 1.10MM; Mfr_name: TEXAS INSTRUMENTS; Mistral Part No: 141009030230-R; Part_type: ICS\DIGITAL\GATES; Project: VOCERA; RoHS: Sb/ Br FREE; Datasheet: Y:\MIS_DATABASE\DATASHEETS\ICS\DIGITAL\GATES\SN74LVC1G.PDF
C7 C8 C66 = CAP: CAP CERAMIC 0.47uF 25V 10% X5R 0805; Chkd/date: MANIRAJA/120218; Crtd /date: MANIRAJA/120218; Custom_Duty: 15%; Customs_HS_Code: 85322990; Distributor_name: DIGIKEY; Distributor_part_number: 587-1290-1-ND; Height: 0.95MM; Mfr_name: TAIYO YUDEN; Mfr_part_number: TMK212BJ474KD-T; Mistral Part No: 120018010009-R; Package: 0805; Part_type: CAPACITORS\CERAMIC; Project: TI_MAXIE_CPB; RoHS: RoHS; Temperature: -55°C+85°C; Tolerance: 10%; Voltage: 25V; Wattage: NA; Weight: 5.5mg; Datasheet: Y:\MIS_DATABASE\DATASHEETS\CAPACITORS\TMK212BJ474KD.PDF
C9 C10 C290 C365 = CAP: CAP CERAMIC 47uF 25V 20% X5R 1206; Chkd/date: MANIRAJA/230118; Crtd /date: MANIRAJA/230118; Custom_Duty: 15%; Customs_HS_Code: 85322990; Distributor_name: DIGIKEY; Distributor_part_number: 490-16268-1-ND; Height: 1.80MM; Mfr_name: MURATA; Mfr_part_number: GRM31CR61E476ME44L; Mistral Part No: 120013050002-R; Package: 1206; Part_type: CAPACITORS\CERAMIC; Project: TI_MAXIE_CPB; RoHS: RoHS; Temperature: -55°C+85°C; Tolerance: 20%; Voltage: 25V; Wattage: NA; Weight: NA; Datasheet: Y:\MIS_DATABASE\DATASHEETS\CAPACITORS\GRM31.PDF
C12 C24 = CAP_POL: CAP ELECTROLYTIC 150uF 25V 20% CASE_8383; Chkd/date: MANIRAJA/240118; Crtd /date: MANIRAJA/240118; Custom_Duty: 15%; Customs_HS_Code: 85322990; Distributor_name: DIGIKEY; Distributor_part_number: 493-2191-1-ND; Height: 10.80MM; Mfr_name: NICHICON; Mfr_part_number: UWT1E151MNL1GS; Mistral Part No: 120018010023-R; Package: CASE_8383; Part_type: CAPACITORS\ELECTROLYTIC; Project: TI_MAXIE_CPB; RoHS: RoHS; Temperature: -55°C+105°C; Tolerance: 20%; Voltage: 25V; Wattage: NA; Weight: NA; Datasheet: Y:\MIS_DATABASE\DATASHEETS\CAPACITORS\UWT-SER.PDF
C48 C308 C350 = CAP: CAP CERAMIC 100pF 50V 10% X7R 0402; Chkd/date: JAGADISH/110314; Crtd /date: SARANYA/110314; Custom_Duty: 15%; Customs_HS_Code: 85322990; Distributor_name: DIGIKEY; Distributor_part_number: 311-1419-1-ND; Height: 0.55MM; Mfr_name: YAGEO; Mfr_part_number: CC0402KRX7R9BB101; Mistral Part No: 120014030006-R; Package: 0402; Part_type: CAPACITORS\CERAMIC; Project: DMP; RoHS: RoHS; Temperature: -55°C+125°C; Tolerance: 10%; Voltage: 50V; Wattage: NA; Weight: NA; Datasheet: Y:\MIS_DATABASE\DATASHEETS\CAPACITORS\YACC0603.PDF
C49 = CAP: CAP CERAMIC 820pF 50V 5% C0G(NP0) 0402; Chkd/date: MANIRAJA/120218; Crtd /date: MANIRAJA/120218; Custom_Duty: 15%; Customs_HS_Code: 85322990; Distributor_name: DIGIKEY; Distributor_part_number: 445-13812-1-ND; Height: 0.55MM; Mfr_name: TDK CORPORATION; Mfr_part_number: C1005NP01H821J050BA; Mistral Part No: 120018010010-R; Package: 0402; Part_type: CAPACITORS\CERAMIC; Project: TI_MAXIE_CPB; RoHS: RoHS; Temperature: -55°C+150°C; Tolerance: 5%; Voltage: 50V; Wattage: NA; Weight: 0.65mg; Datasheet: Y:\MIS_DATABASE\DATASHEETS\CAPACITORS\C1005NP01H821J050BA.PDF
C51 C56 = CAP: CAP CERAMIC 1uF 25V 10% X5R 0603; Chkd/date: MANIRAJA/230118; Crtd /date: MANIRAJA/230118; Custom_Duty: 15%; Customs_HS_Code: 85322990; Distributor_name: DIGIKEY; Distributor_part_number: 478-5142-1-ND; Height: 0.94MM; Mfr_name: AVX CORPORATION; Mfr_part_number: 06033D105KAT2A; Mistral Part No: 120010080040-R; Package: 0603; Part_type: CAPACITORS\CERAMIC; Project: TI_MAXIE_CPB; RoHS: RoHS; Temperature: -55°C+85°C; Tolerance: 10%; Voltage: 25V; Wattage: NA; Weight: 2mg; Datasheet: Y:\MIS_DATABASE\DATASHEETS\CAPACITORS\AVX_MLC.PDF
C62 = CAP: CAP CERAMIC 220pF 25V 5% C0G 0402; Chkd/date: VASANTHA/211215; Crtd /date: VASANTHA/211215; Custom_Duty: 15%; Customs_HS_Code: 85322990; Distributor_name: DIGIKEY; Distributor_part_number: 490-8174-1-ND; Height: 0.55MM; Mfr_name: MURATA; Mfr_part_number: GRM1555C1E221JA01D; Mistral Part No: 120015120016-R; Package: 0402; Part_type: CAPACITORS\CERAMIC; Project: DLRL_NBSDR; RoHS: RoHS; Temperature: -55°C+125°C; Tolerance: 5%; Voltage: 25V; Wattage: NA; Weight: NA; Datasheet: Y:\MIS_DATABASE\DATASHEETS\CAPACITORS\GRM188SERIES.PDF
C63 = CAP: CAP CERAMIC 0.047uF 50V 10% X7R 0402; Chkd/date: MANIRAJA/240118; Crtd /date: MANIRAJA/240118; Custom_Duty: 15%; Customs_HS_Code: 85322990; Distributor_name: DIGIKEY; Distributor_part_number: GRM155R71H473KE14J-ND; Height: 0.55MM; Mfr_name: MURATA; Mfr_part_number: GRM155R71H473KE14J; Mistral Part No: 120018010011-R; Package: 0402; Part_type: CAPACITORS\CERAMIC; Project: TI_MAXIE_CPB; RoHS: RoHS; Temperature: -55°C+125°C; Tolerance: 10%; Voltage: 50V; Wattage: NA; Weight: 6mg; Datasheet: Y:\MIS_DATABASE\DATASHEETS\CAPACITORS\GRM155R71H473KE14.PDF
C68 C680 C681 = CAP: CAP CERAMIC 2.2uF 50V 10% X5R 0805; Chkd/date: MANIRAJA/310818; Crtd /date: MANIRAJA/310818; Custom_Duty: 15%; Customs_HS_Code: 85322990; Distributor_name: DIGIKEY; Distributor_part_number: 445-14407-1-ND; Footprint Path: Y:\MIS_DATABASE\Library\ALTIUM_TOOL\PCB_FOOTPRINTS\Altium_Footprint_Lib.PcbLib; Height: 1.00MM; Library Path: Y:\MIS_DATABASE\Library\ALTIUM_TOOL\SCHEMATICS_PARTS\MS_DISCRETE_Library.schlib; Mfr_name: TDK CORPORATION; Mfr_part_number: C2012X5R1H225K085AB; Mistral Part No: 120018010012-R; Package: 0805; Part_type: CAPACITORS\CERAMIC; Project: TI_MAXIE_CPB; RoHS: RoHS; Temperature: -55°C+85°C; Tolerance: 10%; Voltage: 50V; Wattage: NA; Weight: 5.5mg; Datasheet: Y:\MIS_DATABASE\DATASHEETS\CAPACITORS\TDK_C-SER-JUL17.PDF
C69 = CAP: CAP CERAMIC 10uF 50V 20% X5R 1206; Chkd/date: MANIRAJA/240118; Crtd /date: MANIRAJA/240118; Custom_Duty: 15%; Customs_HS_Code: 85322990; Distributor_name: DIGIKEY; Distributor_part_number: 490-10756-1-ND; Footprint Path: Y:\MIS_DATABASE\Library\ALTIUM_TOOL\PCB_FOOTPRINTS\Altium_Footprint_Lib.PcbLib; Height: 1.80MM; Library Path: Y:\MIS_DATABASE\Library\ALTIUM_TOOL\SCHEMATICS_PARTS\MS_DISCRETE_Library.schlib; Mfr_name: MURATA; Mfr_part_number: GRM31CR61H106MA12L; Mistral Part No: 120018010013-R; Package: 1206; Part_type: CAPACITORS\CERAMIC; Project: TI_MAXIE_CPB; RoHS: RoHS; Temperature: -55°C+85°C; Tolerance: 20%; Voltage: 50V; Wattage: NA; Weight: 40mg; Datasheet: Y:\MIS_DATABASE\DATASHEETS\CAPACITORS\GRM31CR61H106MA12.PDF
C283 C367 = CAP_POL: CAP ELECTROLYTIC 470uF 10V 20% D8CASE_6666; Chkd/date: MANIRAJA/171017; Crtd /date: MANIRAJA/171017; Custom_Duty: 15%; Customs_HS_Code: 85322990; Distributor_name: DIGIKEY; Distributor_part_number: P15094CT-ND; Height: 8.00MM; Mfr_name: PANASONIC; Mfr_part_number: EEE-FTA471XAP; Mistral Part No: 120017100008-R; Package: D8CASE_6666; Part_type: CAPACITORS\ELECTROLYTIC; Project: TI_MAXIE_CPB; RoHS: RoHS; Temperature: -55°C+105°C; Tolerance: 20%; Voltage: 10V; Wattage: NA; Weight: NA; Datasheet: Y:\MIS_DATABASE\DATASHEETS\CAPACITORS\FTV-SER.PDF
C284 C368 = CAP_POL: CAP POLMER 270uF 10V 20% SMD; Chkd/date: MANIRAJA/240118; Crtd /date: MANIRAJA/240118; Custom_Duty: 15%; Customs_HS_Code: 85322990; Distributor_name: DIGIKEY; Distributor_part_number: 732-6414-1-ND; Height: 7.7MM; Mfr_name: WURTH ELECTRONICS; Mfr_part_number: 875105245014; Mistral Part No: 120018010024-R; Package: SMD; Part_type: CAPACITORS\POLYPROPYLENE; Project: TI_MAXIE_CPB; RoHS: RoHS; Temperature: -55°C+105°C; Tolerance: 20%; Voltage: 10V; Wattage: NA; Weight: NA; Datasheet: Y:\MIS_DATABASE\DATASHEETS\CAPACITORS\875105245014.PDF
C307 C352 = CAP: CAP CERAMIC 0.01uF 10V 10% X7R 0402; Chkd/date: VASANTHA/061216; Crtd /date: MAZHAR/201005; Custom_Duty: 15%; Customs_HS_Code: 85322990; Distributor_name: DIGIKEY; Distributor_part_number: 478-7890-1-ND; Height: 0.56MM; Mfr_name: AVX CORPORATION; Mfr_part_number: 0402ZC103KAT2A; Mistral Part No: 120009030017-R; Package: 0402; Part_type: CAPACITORS\CERAMIC; Project: ADR; RoHS: RoHS; Temperature: -55°C+125°C; Tolerance: 10%; Voltage: 10V; Wattage: NA; Weight: 0.65mg; Datasheet: Y:\MIS_DATABASE\DATASHEETS\CAPACITORS\AVX_MLC.PDF
C317 C345 = CAP: CAP CERAMIC 0.056uF 10V 10% X5R 0402; Chkd/date: MANIRAJA/240118; Crtd /date: MANIRAJA/240118; Custom_Duty: 15%; Customs_HS_Code: 85322990; Distributor_name: DIGIKEY; Distributor_part_number: 490-5413-1-ND; Height: 0.55MM; Mfr_name: MURATA; Mfr_part_number: GRM155R61A563KA01D; Mistral Part No: 120018010014-R; Package: 0402; Part_type: CAPACITORS\CERAMIC; Project: TI_MAXIE_CPB; RoHS: RoHS; Temperature: -55°C+85°C; Tolerance: 10%; Voltage: 10V; Wattage: NA; Weight: 6mg; Datasheet: Y:\MIS_DATABASE\DATASHEETS\CAPACITORS\GRM155R61A563KA01.PDF
C318 = CAP: CAP CERAMIC 0.47uF 25V 10% X7R 0603; Chkd/date: MANIRAJA/240118; Crtd /date: MANIRAJA/240118; Custom_Duty: 15%; Customs_HS_Code: 85322990; Distributor_name: DIGIKEY; Distributor_part_number: 311-1805-1-ND; Height: 0.87MM; Mfr_name: YAGEO AMERICA; Mfr_part_number: CC0603KRX7R8BB474; Mistral Part No: 120009030111-R; Package: 0603; Part_type: CAPACITORS\CERAMIC; Project: TI_MAXIE_CPB; RoHS: RoHS; Temperature: -55°C+125°C; Tolerance: 10%; Voltage: 25V; Wattage: NA; Weight: 2mg; Datasheet: Y:\MIS_DATABASE\DATASHEETS\CAPACITORS\YACC0603.PDF
C325 = CAP: CAP CERAMIC 1uF 16V 20% X5R 0402; Chkd/date: MANIRAJA/150218; Crtd /date: ALVY/150218; Custom_Duty: 15%; Customs_HS_Code: 85322990; Distributor_name: DIGIKEY; Distributor_part_number: 587-5514-1-ND; Footprint Path: Y:\MIS_DATABASE\Library\ALTIUM_TOOL\PCB_FOOTPRINTS\Altium_Footprint_Lib.PcbLib; Height: 0.55MM; Library Path: Y:\MIS_DATABASE\Library\ALTIUM_TOOL\SCHEMATICS_PARTS\MS_DISCRETE_Library.schlib; Mfr_name: TAIYO YUDEN; Mfr_part_number: EMK105BJ105MV-F; Mistral Part No: 120018020006-R; Package: 0402; Part_type: CAPACITORS\CERAMIC; Project: TI_MAXIE_CPB; RoHS: RoHS; Temperature: -55°C+85°C; Tolerance: 20%; Voltage: 16V; Wattage: NA; Weight: 0.65mg; Datasheet: Y:\MIS_DATABASE\DATASHEETS\CAPACITORS\EMK105BJ105MV-F.PDF
C330 C679 = CAP: CAP CERAMIC 4.7uF 10V 20% X5R 0402; Chkd/date: MANIRAJA/230118; Crtd /date: MANIRAJA/230118; Custom_Duty: 15%; Customs_HS_Code: 85322990; Distributor_name: DIGIKEY; Distributor_part_number: 478-10791-1-ND; Height: 0.71MM; Mfr_name: AVX CORPORATION; Mfr_part_number: 0402ZD475MAT2A; Mistral Part No: 120012060002-R; Package: 0402; Part_type: CAPACITORS\CERAMIC; Project: TI_MAXIE_CPB; RoHS: RoHS; Temperature: -55°C+85°C; Tolerance: 20%; Voltage: 10V; Wattage: NA; Weight: 0.65mg; Datasheet: Y:\MIS_DATABASE\DATASHEETS\CAPACITORS\AVX_MLC.PDF
C340 = CAP: CAP CERAMIC 0.47uF 50V 5% X7R 0805; Chkd/date: MANIRAJA/240118; Crtd /date: MANIRAJA/240118; Custom_Duty: 15%; Customs_HS_Code: 85322990; Distributor_name: MOUSER; Distributor_part_number: 603-CC0805JK7R9BB474; Height: 1.35MM; Mfr_name: YAGEO AMERICA; Mfr_part_number: CC0805JKX7R9BB474; Mistral Part No: 120018010019-R; Package: 0805; Part_type: CAPACITORS\CERAMIC; Project: TI_MAXIE_CPB; RoHS: RoHS; Temperature: -55°C+125°C; Tolerance: 5%; Voltage: 50V; Wattage: NA; Weight: 5.5mg; Datasheet: Y:\MIS_DATABASE\DATASHEETS\CAPACITORS\YACC0603.PDF
C683 C684 = CAP: CAP CERAMIC 33pF 50V 2% C0G(NP0) 0201; Chkd/date: MANIRAJA/240118; Crtd /date: MANIRAJA/240118; Custom_Duty: 15%; Customs_HS_Code: 85322990; Distributor_name: DIGIKEY; Distributor_part_number: 490-11325-1-ND; Height: 0.33MM; Mfr_name: MURATA; Mfr_part_number: GRM0335C1H330GA01D; Mistral Part No: 120018010015-R; Package: 0201; Part_type: CAPACITORS\CERAMIC; Project: TI_MAXIE_CPB; RoHS: RoHS; Temperature: -55°C+125°C; Tolerance: 2%; Voltage: 50V; Wattage: NA; Weight: 0.33mg; Datasheet: Y:\MIS_DATABASE\DATASHEETS\CAPACITORS\GRM0335C1H330GA01.PDF
D3 D5 D8 D9 = DIODE_SCHOTTKY: DIODE SCHOTTKY RECTIFIER 40V 4A DO-214AA(SMB); Chkd/date: MANIRAJA/171017; Crtd /date: MANIRAJA/171017; Custom_Duty: 15%; Customs_HS_Code: 85412900; Distributor_name: DIGIKEY; Distributor_part_number: SSB44-E3/52TGICT-ND; Height: 2.44MM; Mfr_name: VISHAY; Mistral Part No: 130017100021-R; Package: DO-214AA; Part_type: DIODE\SCHOTTKY; Project: TI_MAXIE_CPB; RoHS: RoHS; Temperature: -65°C+150°C; Tolerance: NA; Voltage: NA; Wattage: NA; Weight: 180mg; Datasheet: Y:\MIS_DATABASE\DATASHEETS\DISCRETES\DIODES\SSB4XX.PDF
D15 D17 = DIODE_SCHOTTKY: DIODE SCHOTTKY 40V 1A SOD323A; Chkd/date: MANIRAJA/150218; Crtd /date: ALVY/150218; Custom_Duty: 24%; Customs_HS_Code: 85437099; Distributor_name: DIGIKEY; Distributor_part_number: 893-1188-1-ND; Footprint Path: Y:\MIS_DATABASE\Library\ALTIUM_TOOL\PCB_FOOTPRINTS\Altium_Footprint_Lib.PcbLib; Height: 1.00MM; Library Path: Y:\MIS_DATABASE\Library\ALTIUM_TOOL\SCHEMATICS_PARTS\MS_DISCRETE_Library.schlib; Mfr_name: TOREX; Mfr_part_number: XBS104S13R-G; Mistral Part No: 130018020038-R; Package: SOD323; Part_type: DIODE\SCHOTTKY; Project: TI_MAXIE_CPB; RoHS: RoHS; Temperature: NA; Tolerance: NA; Voltage: 40V; Wattage: NA; Weight: NA; Datasheet: Y:\MIS_DATABASE\DATASHEETS\DISCRETES\DIODES\XBS104S13R-G.PDF
L1 = INDUCTOR: IND POWER 10uH 5.7A 20% SMD; Chkd/date: MANIRAJA/171017; Crtd /date: MANIRAJA/171017; Custom_Duty: 24%; Customs_HS_Code: 85437099; Distributor_name: DIGIKEY; Distributor_part_number: P17067CT-ND; Height: 5.40MM; Mfr_name: PANASONIC; Mfr_part_number: ETQ-P5M100YFM; Mistral Part No: 130017100020-R; Package: SMD; Project: TI_MAXIE_CPB; RoHS: RoHS; Temperature: -40°C+150°C; Tolerance: 20%; Voltage: NA; Wattage: NA; Weight: NA; Datasheet: Y:\MIS_DATABASE\DATASHEETS\DISCRETES\INDUCTORS\ETQ-P5XX-SER.PDF
L8 L10 = INDUCTOR: IND POWER 1.5uH 15.1A 20% SMD; Chkd/date: MANIRAJA/171017; Crtd /date: MANIRAJA/171017; Custom_Duty: 24%; Customs_HS_Code: 85437099; Distributor_name: DIGIKEY; Distributor_part_number: PCD2466CT-ND; Height: 4.00MM; Mfr_name: PANASONIC; Mfr_part_number: ETQ-P4M1R5KVK; Mistral Part No: 130017100018-R; Package: SMD; Project: TI_MAXIE_CPB; RoHS: RoHS; Temperature: -55°C+155°C; Tolerance: 20%; Voltage: NA; Wattage: NA; Weight: NA; Datasheet: Y:\MIS_DATABASE\DATASHEETS\DISCRETES\INDUCTORS\ETQPXX-SER.PDF
LD2-LD4 = LED_598-8170-107F: LED ALINGAP GREEN CLEAR 0805; Chkd/date: MANIRAJA/230817; Crtd /date: SARANYA/070514; Custom_Duty: 24%; Customs_HS_Code: 85437099; Distributor_name: DIGIKEY; Distributor_part_number: 350-2044-1-ND; Height: 0.70MM; Mfr_name: DIALIGHT; Mistral Part No: 130014050065-R; Package: 0805; Part_type: OPTO\LED; Project: AEGIS GP BETA2; RoHS: RoHS; Temperature: -30°C+85°C; Tolerance: NA; Voltage: NA; Wattage: NA; Weight: NA; Datasheet: Y:\MIS_DATABASE\DATASHEETS\DISCRETES\LEDS\598-SER.PDF
R1 R3 = RESISTOR: RES 220E 1/16W 5% 0402; Chkd/date: VASANTHA/291216; Crtd /date: GEETHA/260406; Custom_Duty: 15%; Customs_HS_Code: 85332119; Distributor_name: DIGIKEY; Distributor_part_number: P220JCT-ND; Footprint Path: Y:\MIS_DATABASE\Library\ALTIUM_TOOL\PCB_FOOTPRINTS\Altium_Footprint_Lib.PcbLib; Height: 0.40MM; Library Path: Y:\MIS_DATABASE\Library\ALTIUM_TOOL\SCHEMATICS_PARTS\MS_DISCRETE_Library.schlib; Mfr_name: PANASONIC-ECG; Mfr_part_number: ERJ-2GEJ221X; Mistral Part No: 110009030506-R; Package: 0402; Part_type: RESISTORS\FIXED; Project: RED EYE; RoHS: RoHS; Temperature: -55°C+155°C; Tolerance: 5%; Voltage: NA; Wattage: 1/16W; Weight: 0.8g/1000pcs; Datasheet: Y:\MIS_DATABASE\DATASHEETS\RESISTORS\ERJ12.PDF
R2 = RESISTOR: RES 1K 1/20W 5% 0201; Chkd/date: JEBRAN/110815; Crtd /date: JEBRAN/110815; Custom_Duty: 15%; Customs_HS_Code: 85332119; Distributor_name: DIGIKEY; Distributor_part_number: 541-1.00KAABCT-ND; Height: 0.28MM; Mfr_name: VISHAY; Mfr_part_number: CRCW02011K00FKED; Mistral Part No: 110015080014-R; Package: 0201; Part_type: RESISTORS\FIXED; Project: OCTASIC_3000; RoHS: RoHS; Temperature: -55°C+155°C; Tolerance: 5%; Voltage: NA; Wattage: 1/20W; Weight: NA; Datasheet: Y:\MIS_DATABASE\DATASHEETS\RESISTORS\CRCW0201.PDF
R53 = RESISTOR: RES 1K 1/10W 1% 0402; Chkd/date: VASANTHA/281216; Crtd /date: MAZHAR/150506; Cust_part_number: 4700-80039E; Custom_Duty: 15%; Customs_HS_Code: 85332119; Distributor_name: DIGIKEY; Distributor_part_number: P1.00KLCT-ND; Footprint Path: Y:\MIS_DATABASE\Library\ALTIUM_TOOL\PCB_FOOTPRINTS\Altium_Footprint_Lib.PcbLib; Height: 0.40MM; Library Path: Y:\MIS_DATABASE\Library\ALTIUM_TOOL\SCHEMATICS_PARTS\MS_DISCRETE_Library.schlib; Mfr_name: PANASONIC-ECG; Mfr_part_number: ERJ-2RKF1001X; Mistral Part No: 110009030411-R; Package: 0402; Part_type: RESISTORS\FIXED; Project: VOCERA; RoHS: RoHS; Temperature: -55°C+125°C; Tolerance: 1%; Voltage: NA; Wattage: 1/10W; Weight: 0.8g/1000pcs; Datasheet: Y:\MIS_DATABASE\DATASHEETS\RESISTORS\ERJ-2R.PDF
R54 = RESISTOR: RES 8.66K 1/10W 1% 0402; Chkd/date: JEBRAN/260315; Crtd /date: CHAITHANYA/260912; Custom_Duty: 15%; Customs_HS_Code: 85332119; Distributor_name: DIGIKEY; Distributor_part_number: P8.66KLCT-ND; Height: 0.40MM; Mfr_name: PANASONIC; Mfr_part_number: ERJ-2RKF8661X; Mistral Part No: 110012090010-R; Package: 0402; Part_type: RESISTORS\FIXED; Project: ICP; RoHS: RoHS; Temperature: -55°C+155°C; Tolerance: 1%; Voltage: NA; Wattage: 1/10W; Weight: 0.8/1000g; Datasheet: Y:\MIS_DATABASE\DATASHEETS\RESISTORS\ERJ-2R.PDF
R55 = RESISTOR: RES 46.4K 1/16W 1% 0402; Chkd/date: USMAN/230413; Crtd /date: USMAN/180213; Custom_Duty: 15%; Customs_HS_Code: 85332119; Distributor_name: DIGIKEY; Distributor_part_number: 541-46.4KLCT-ND; Footprint Path: Y:\MIS_DATABASE\Library\ALTIUM_TOOL\PCB_FOOTPRINTS\Altium_Footprint_Lib.PcbLib; Height: 0.40MM; Library Path: Y:\MIS_DATABASE\Library\ALTIUM_TOOL\SCHEMATICS_PARTS\MS_DISCRETE_Library.schlib; Mfr_name: VISHAY; Mfr_part_number: CRCW040246K4FKED; Mistral Part No: 110013020001-R; Package: 0402; Part_type: RESISTORS\FIXED; Project: ITS-SCP; RoHS: RoHS; Temperature: -55°C+155°C; Tolerance: 1%; Voltage: NA; Wattage: 1/16W; Weight: 0.65mg; Datasheet: Y:\MIS_DATABASE\DATASHEETS\RESISTORS\CRCW0603.PDF
R62 = RESISTOR: RES 0.028E 1W 2% 1508; Chkd/date: MANIRAJA/280917; Crtd /date: MANIRAJA/280917; Custom_Duty: 15%; Customs_HS_Code: 85332119; Distributor_name: DIGIKEY; Distributor_part_number: 408-1717-1-ND; Height: 0.70MM; Mfr_name: SUSUMU; Mfr_part_number: RL3720WT-R028-G; Mistral Part No: 110017090012-R; Package: 1508; Part_type: RESISTORS\FIXED; Project: TI_MAXIE_CPB; RoHS: RoHS; Temperature: -55°C+125°C; Tolerance: 2%; Voltage: NA; Wattage: 1W; Weight: NA; Datasheet: Y:\MIS_DATABASE\DATASHEETS\RESISTORS\RL3720W-SER.PDF
R65 = RESISTOR: RES 18.2K 1/16W 1% 0402; Chkd/date: MAZHAR/150709; Crtd /date: USMAN/130309; Custom_Duty: 15%; Customs_HS_Code: 85332119; Distributor_name: DIGIKEY; Distributor_part_number: P18.2KLCT-ND; Height: 0.40MM; Mfr_name: PANASONIC-ECG; Mfr_part_number: ERJ-2RKF1822X; Mistral Part No: 110009031211-R; Package: 0402; Part_type: RESISTORS\FIXED; Project: AXON; RoHS: RoHS; Tolerance: 1%; Wattage: 1/16W; Datasheet: Y:\MIS_DATABASE\DATASHEETS\RESISTORS\PAN-ERJSERIES.PDF
R68 = RESISTOR: RES 75K 1/10W 1% 0402; Chkd/date: MANIRAJA/040418; Crtd /date: MAZHAR/120505; Custom_Duty: 15%; Customs_HS_Code: 85332119; Distributor_name: DIGIKEY; Distributor_part_number: P75.0KLCT-ND; Footprint Path: Y:\MIS_DATABASE\Library\ALTIUM_TOOL\PCB_FOOTPRINTS\Altium_Footprint_Lib.PcbLib; Height: 0.40MM; Library Path: Y:\MIS_DATABASE\Library\ALTIUM_TOOL\SCHEMATICS_PARTS\MS_DISCRETE_Library.schlib; Mfr_name: PANASONIC-ECG; Mfr_part_number: ERJ-2RKF7502X; Mistral Part No: 110009031116-R; Package: 0402; Part_type: RESISTORS\FIXED; Project: G4_SVGA; RoHS: RoHS; Temperature: -55°C+155°C; Tolerance: 1%; Voltage: NA; Wattage: 1/10W; Weight: 0.8mg; Datasheet: Y:\MIS_DATABASE\DATASHEETS\RESISTORS\PAN-ERJSERIES.PDF
R357 R426 = RESISTOR: RES 0.005E 1/2W 1% 1206; Chkd/date: SUHAS/290910; Crtd /date: USMAN/190908; Custom_Duty: 15%; Customs_HS_Code: 85332119; Distributor_name: DIGIKEY; Distributor_part_number: WSLD-.005CT-ND; Height: 0.89MM; Mfr_name: VISHAY; Mfr_part_number: WSL12065L000FEA18; Mistral Part No: 110009030043-P; Package: 1206; Part_type: RESISTORS\FIXED; Project: MDI; RoHS: Pb-Free; Temperature: -65°C+170°C; Tolerance: 1%; Wattage: 1/2W; Weight: 16.2g/1000pcs; Datasheet: Y:\MIS_DATABASE\DATASHEETS\RESISTORS\WSL-SERIES.PDF
R375 = RESISTOR: RES 19.6K 1/16W 0.1% 0402; Chkd/date: BAVISH/131011; Crtd /date: CHAITHANYA/121011; Custom_Duty: 15%; Customs_HS_Code: 85332119; Distributor_name: DIGIKEY; Distributor_part_number: TNP19.6KDACT-ND; Height: 0.40MM; Mfr_name: VISHAY; Mfr_part_number: TNPW040219K6BEED; Mistral Part No: 110011100020-R; Package: 0402; Part_type: RESISTORS\FIXED; Project: VP-4000-PROCESSOR; RoHS: RoHS; Temperature: -55°C+125°C; Tolerance: 0.1%; Voltage: NA; Wattage: 1/16W; Weight: 0.65/1000g; Datasheet: Y:\MIS_DATABASE\DATASHEETS\RESISTORS\VISHAY_TNPW.PDF
R376 R404 = RESISTOR: RES 100K 1/16W 5% 0402; Chkd/date: VASANTHA/061216; Crtd /date: BAVISH/010611; Custom_Duty: 15%; Customs_HS_Code: 85332119; Distributor_name: DIGIKEY; Distributor_part_number: 541-100KJCT-ND; Height: 0.40MM; Mfr_name: VISHAY; Mfr_part_number: CRCW0402100KJNED; Mistral Part No: 110011060002-R; Package: 0402; Part_type: RESISTORS\FIXED; Project: AM4515_EVM_LCD; RoHS: RoHS; Temperature: -55°C+155°C; Tolerance: 5%; Voltage: NA; Wattage: 1/16W; Weight: 0.65mg; Datasheet: Y:\MIS_DATABASE\DATASHEETS\RESISTORS\CRCW0603.PDF
R378 R384 R387 R392 R396 R405 = RESISTOR: RES 10.2E 1/16W 1% 0402; Chkd/date: MANIRAJA/030817; Crtd /date: MANIRAJA/030817; Custom_Duty: 15%; Customs_HS_Code: 85332119; Distributor_name: DIGIKEY; Distributor_part_number: 541-10.2LCT-ND; Height: 0.40MM; Mfr_name: VISHAY; Mfr_part_number: CRCW040210R2FKED; Mistral Part No: 110017080001-R; Package: 0402; Part_type: RESISTORS\FIXED; Project: TI_SVB_DUT; RoHS: RoHS; Temperature: -55°C+155°C; Tolerance: 1%; Voltage: NA; Wattage: 1/16W; Weight: 0.65mg; Datasheet: Y:\MIS_DATABASE\DATASHEETS\RESISTORS\CRCW0603.PDF
R399 = RESISTOR: RES 29.4K 1/16W 1% 0402; Chkd/date: SHREESHAIL/121205; Crtd /date: MAZHAR/120505; Custom_Duty: 15%; Customs_HS_Code: 85332119; Distributor_name: DIGIKEY; Distributor_part_number: P29.4KLTR-ND; Height: 0.40MM; Mfr_name: PANASONIC-ECG; Mfr_part_number: ERJ-2RKF2942X; Mistral Part No: 110009030592-R; Package: 0402; Part_type: RESISTORS\FIXED; Project: CTP02_REVA_BASE; RoHS: RoHS; Tolerance: 1%; Wattage: 1/16W; Datasheet: Y:\MIS_DATABASE\DATASHEETS\RESISTORS\PAN_ERJ.PDF
R701 R703 = RESISTOR: RES 49.9E 1/20W 1% 0201; Chkd/date: MAZHAR/140709; Crtd /date: MAZHAR/300807; Custom_Duty: 15%; Customs_HS_Code: 85332119; Distributor_name: DIGIKEY; Distributor_part_number: P49.9ABCT-ND; Footprint Path: Y:\MIS_DATABASE\Library\ALTIUM_TOOL\PCB_FOOTPRINTS\Altium_Footprint_Lib.PcbLib; Height: 0.26MM; Library Path: Y:\MIS_DATABASE\Library\ALTIUM_TOOL\SCHEMATICS_PARTS\MS_DISCRETE_Library.schlib; Mfr_name: PANASONIC-ECG; Mfr_part_number: ERJ-1GEF49R9C; Mistral Part No: 110009030893-R; Package: 0201; Part_type: RESISTORS\FIXED; Project: V8TS; RoHS: RoHS; Tolerance: 1%; Wattage: 1/20W; Datasheet: Y:\MIS_DATABASE\DATASHEETS\RESISTORS\ERJ-1G.PDF
TP1 TP7 TP66 = TESTPOINT: TESTPOINT 1.0MM DRILL PTH; Chkd/date: MAZHAR/271211; Crtd /date: SHREESHAIL/041005; Distributor_name: NA; Distributor_part_number: NA; Height: NA; Mfr_name: LOCAL; Mistral Part No: 130009030938; Package: THRU-HOLE; Part_type: MISC\TESTPOINT; Project: HSE; Datasheet: NA
U13 U18 = MOSFET_SI4442DY: IC MOSFET N-CHANNEL 30V 15A SOIC8; Chkd/date: MANIRAJA/130617; Crtd /date: USMAN/121208; Custom_Duty: 15%; Customs_HS_Code: 85423100; Distributor_name: MOUSER; Distributor_part_number: 781-SI4442DY; Height: 1.75MM; Mfr_name: VISHAY; Mistral Part No: 142009030189-R; Package: SOIC8; Part_type: ICS\POWER\MOSFET; Project: KHAN_MAIN; RoHS: RoHS; Temperature: -55°C+150°C; Tolerance: NA; Voltage: NA; Wattage: NA; Weight: 85mg; Datasheet: Y:\MIS_DATABASE\DATASHEETS\DISCRETES\TRANSISTORS_FETS\SI4442DY.PDF
U14 = LM25118MH_HTSSOP20: IC WIDE VOLTAGE BUCK BOOST CONTROLLER HTSSOP20; Chkd/date: MANIRAJA/250917; Crtd /date: MANIRAJA/250917; Custom_Duty: 15%; Customs_HS_Code: 85423100; Distributor_name: DIGIKEY; Distributor_part_number: 296-38995-ND; Height: 1.10MM; Mfr_name: TEXAS INSTRUMENTS; Mistral Part No: 142017090017-R; Package: HTSSOP20; Part_type: ICS\POWER\VOLTAGE REGULATOR; Project: TI_MAXIE_CPB; RoHS: RoHS; Temperature: -40°C+125°C; Tolerance: NA; Voltage: NA; Wattage: NA; Weight: 81.8mg; Datasheet: Y:\MIS_DATABASE\DATASHEETS\ICS\POWER\LM25118MH.PDF
U71 U72 U78 U81 = MOSFET_CSD18501Q5A: IC MOSFET N-CHANNEL 60V VSONP8; Chkd/date: MANIRAJA/041017; Crtd /date: MANIRAJA/041017; Custom_Duty: 15%; Customs_HS_Code: 85423100; Distributor_name: DIGIKEY; Distributor_part_number: 296-47321-1-ND; Height: 0.90MM; Mfr_name: TEXAS INSTRUMENTS; Mistral Part No: 142017100004-R; Package: VSONP8; Part_type: ICS\POWER\MOSFET; Project: TI_MAXIE_CPB; RoHS: RoHS; Temperature: -55°C+150°C; Tolerance: NA; Voltage: 60V; Wattage: NA; Weight: NA; Datasheet: Y:\MIS_DATABASE\DATASHEETS\ICS\POWER\CSD18543Q3A.PDF
U75 = LM5140QRWGTQ1_VQFNP40: IC WIDE I/P DUAL SYNCHRONOUS BUCK CONTROLLER VQFNP40; Chkd/date: MANIRAJA/041017; Crtd /date: MANIRAJA/041017; Custom_Duty: 15%; Customs_HS_Code: 85423100; Distributor_name: DIGIKEY; Distributor_part_number: 296-43790-1-ND; Height: 0.90MM; Mfr_name: TEXAS INSTRUMENTS; Mistral Part No: 142017100003-R; Package: VQFNP40; Part_type: ICS\POWER\CONVERTER; Project: TI_MAXIE_CPB; RoHS: RoHS; Temperature: -40°C+150°C; Tolerance: NA; Voltage: NA; Wattage: NA; Weight: 104mg; Datasheet: Y:\MIS_DATABASE\DATASHEETS\ICS\POWER\LM5140QRWGXX.PDF

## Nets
DGND: C7.2 C8.2 C9.2 C10.2 C12.2 C24.2 C51.2 C56.2 C62.2 C63.2 C68.2 C69.2 C168.2 C179.2 C231.2 C232.2 C234.2 C243.2 C283.2 C284.2 C290.2 C307.2 C308.2 C316.2 C317.2 C318.2 C325.1 C330.2 C340.2 C345.2 C350.2 C352.2 C365.2 C367.2 C368.2 C679.2 C680.2 C681.2 D11.2(A) LD2.1 LD3.1 LD4.1 Q7.3(D) R53.2 R62.2 R64.2 R65.2 R201.2 R300.2 SW8.3 SW8.4 SW8.5(GND) U13.1(S1) U13.2(S2) U13.3(S3) U14.6(AGND) U14.13(CSG) U14.14(PGND) U14.21(EP) U35.2(GND) U35.4(GND) U35.6(GND) U49.2(GND) U50.2(GND) U71.1(S1) U71.2(S2) U71.3(S3) U75.14(PGND2) U75.17(PGND1) U75.35(AGND) U75.38(SYNIN) U75.41(EP) U81.1(S1) U81.2(S2) U81.3(S3) ; also on sheet 11 12 13 14 15 16 17 18 19 20 21 22 23 24 25 26 27 28 29 30 31 32 33 34 35 36 37 38 41 42 43 44
VCC3V3_IO: C234.1 R210.1 R289.1 R319.2 U50.5(VCC) ; also on sheet 11 18 19 20 21 22 23 24 25 26 28 29 30 31 33 34 35 36 37 38 41 42 44
VCC3V3_PREREG: C231.1 C283.1 C284.1 C290.1 R3.1 R357.1 R376.2 R702.1 TP1.1(TP) U49.6(VCC) ; also on sheet 13 41 42
VCC3V3_PREREG_PG: C316.1 R376.1 U75.24(PG1) ; also on sheet 42
VCC5V0_PG: R404.1 U75.7(PG2)
VCC_5V0: C365.1 C367.1 C368.1 R1.1 R426.2 R704.1 TP7.1(TP) U75.6(VCCX) ; also on sheet 30 33 35 44
VCC_12V0: C7.1 C8.1 C9.1 C10.1 C12.1 C24.1 C56.1 D3.1(CATHODE) D5.1(CATHODE) R2.1 R54.1 TP66.1(TP) U14.10(VOUT) U14.17(VCCX) ; also on sheet 35 43
VCC_LM5140: C330.1 C679.1 D15.2(ANODE) D17.2(ANODE) U75.15(VCC) U75.16(VCC)
VDD_MPU: R476.1 ; also on sheet 12 26 41
VDDA_LM5140: C318.1 R404.2 U75.3(FB2) U75.28(FB1) U75.33(DEMB) U75.34(ILSET) U75.36(VDDA) U75.37(OSC)
VIN_MON_PORz_3V3_PG: R210.2 U35.1(OUT) U50.3(B) ; also on sheet 41 42
BOOST_DRIVE: U13.4(G) U14.15(LO)
BUCK_DRIVE: U14.19(HO) U18.4(G)
COMP: C48.1 R55.1 U14.9(COMP)
CS: D8.2(ANODE) D9.2(ANODE) R62.1 U14.12(CS)
FB: C48.2 C49.2 R53.1 R54.2 U14.8(FB)
HB: C66.1 U14.18(HB)
HS: C66.2 D8.1(CATHODE) D9.1(CATHODE) L1.1 U14.20(HS) U18.1(S1) U18.2(S2) U18.3(S3)
HS_L: D3.2(ANODE) D5.2(ANODE) L1.2 U13.5(D1) U13.6(D2) U13.7(D3) U13.8(D4)
JTAG_EMU_RSTn: U50.6(C) ; also on sheet 29
LM5140_COMP1: C308.1 R375.2 U75.29(COMP1)
LM5140_COMP2: C350.1 R399.2 U75.2(COMP2)
RAMP: C62.1 U14.5(RAMP)
RT: R65.1 U14.3(RT)
SoC_PORz: R299.2 TP28.1(TP) ; also on sheet 34 35
SOC_POWER_MON_PORz: R289.2 U49.4(SENSE_OUT) U50.1(A)
SS: C63.1 U14.7(SS)
SUPERVISOR_DEBOUNCE_RSTn: C243.1 D11.1(K) Q7.2(S) R319.1 SW8.1 SW8.2 ; also on sheet 24
SUPERVISOR_MR_RSTn: U49.1(ENABLE) ; also on sheet 24
TEST_PORZn: Q7.1(G) ; also on sheet 24
UVLO_REF: R64.1 R68.2 U14.2(UVLO)
VMAIN: C68.1 C69.1 C179.1 C340.1 C680.1 C681.1 R68.1 R200.1 U14.1(VIN) U14.4(EN) U18.5(D1) U18.6(D2) U18.7(D3) U18.8(D4) U35.5(VDD) U72.5(D) U75.25(VIN) U75.31(EN1) U75.40(EN2) U78.5(D) ; also on sheet 42 43
N18046866: C51.1 U14.16(VCC)
N18046972: C49.1 R55.2
N18289329: R300.1 R476.2 U49.3(SENSE)
N18289350: C232.1 U49.5(CT)
N18292398: C168.1 R200.2 R201.1 U35.3(SENSE)
N19158110: R299.1 U50.4(Y)
N19753713: C343.2 D17.1(CATHODE) U75.11(HB2)
N19753729: C343.1 L10.1 U75.10(SW2) U78.1(S1) U78.2(S2) U78.3(S3) U81.5(D)
N19753760: L10.2 R426.1 R703.1
N19753772: R405.2 U75.8(HOL2) U78.4(G)
N19753820: R392.1 U75.13(LO2)
N19753822: R392.2 R396.2 U81.4(G)
N19753872: C684.1 R703.2 U75.4(CS2)
N19753878: C684.2 R704.2 U75.5(VOUT2)
N19753964: C352.1 R399.1
N19754006: C317.1 U75.30(SS1)
N19754185: C345.1 U75.1(SS2)
N19754201: C320.2 L8.2 U71.5(D) U72.1(S1) U72.2(S2) U72.3(S3) U75.21(SW1)
N19754203: C320.1 D15.1(CATHODE) U75.20(HB1)
N19754223: R378.2 U75.22(HO1)
N19754237: R378.1 U72.4(G) U75.23(HOL1)
N19754314: R384.1 R387.1 U71.4(G)
N19754320: R384.2 U75.19(LOL1)
N19754322: R387.2 U75.18(LO1)
N19754431: R405.1 U75.9(HO2)
N19754435: R396.1 U75.12(LOL2)
N19754522: L8.1 R357.2 R701.1
N19754526: C683.1 R702.2 U75.26(VOUT1)
N19754534: C683.2 R701.2 U75.27(CS1)
N19754630: C325.2 U75.32(RES)
N19754677: C307.1 R375.1
N22749073: LD2.2 R1.2
N22749074: LD3.2 R3.2
N22749075: LD4.2 R2.2

Not connected (* = marked no-connect by the designer): U14 11(SYNC)*; U75 39(SYNOUT)*

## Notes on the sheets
sheet 39
- VOLTAGE SUPERVISOR
- Under Voltage Monitor (VMAIN)
- 40us delay by default
- VDD < 11V asserts PORz
- Under Voltage Monitor (VDD_MPU)
- 40us delay by default
- VCC < 0.9 asserts PORz
sheet 40
- PRE_REG POWER SUPPLY
- 5V,10A and 3.3V,10A Dual SUPPLY
- SERDES  POWER SUPPLY
- 12V,3A SUPPLY
